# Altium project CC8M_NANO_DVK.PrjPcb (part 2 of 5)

## Sheet 06 - CCIMX8M Nano RF, PCIe.SchDoc: CCIMX8M Nano RF, PCIe
size A3; PageSetup: Record=PageOptions¦CenterHorizontal=True¦CenterVertical=True¦PrintScale=0.70¦XCorrection=1.00¦YCorrection=1.00¦PrintKind=0¦BorderSize=5000000¦LeftOffset=0¦BottomOffset=0¦Orientation=2¦PaperLength=4200¦PaperWidth=2970¦Scale=100¦PaperSource=7¦PrintQuality=600¦MediaType=1¦DitherType=10¦PaperKind=A4¦PrintScaleMode=1; Author: Juan Anzola; SheetNumber: 6; SheetTotal: 21

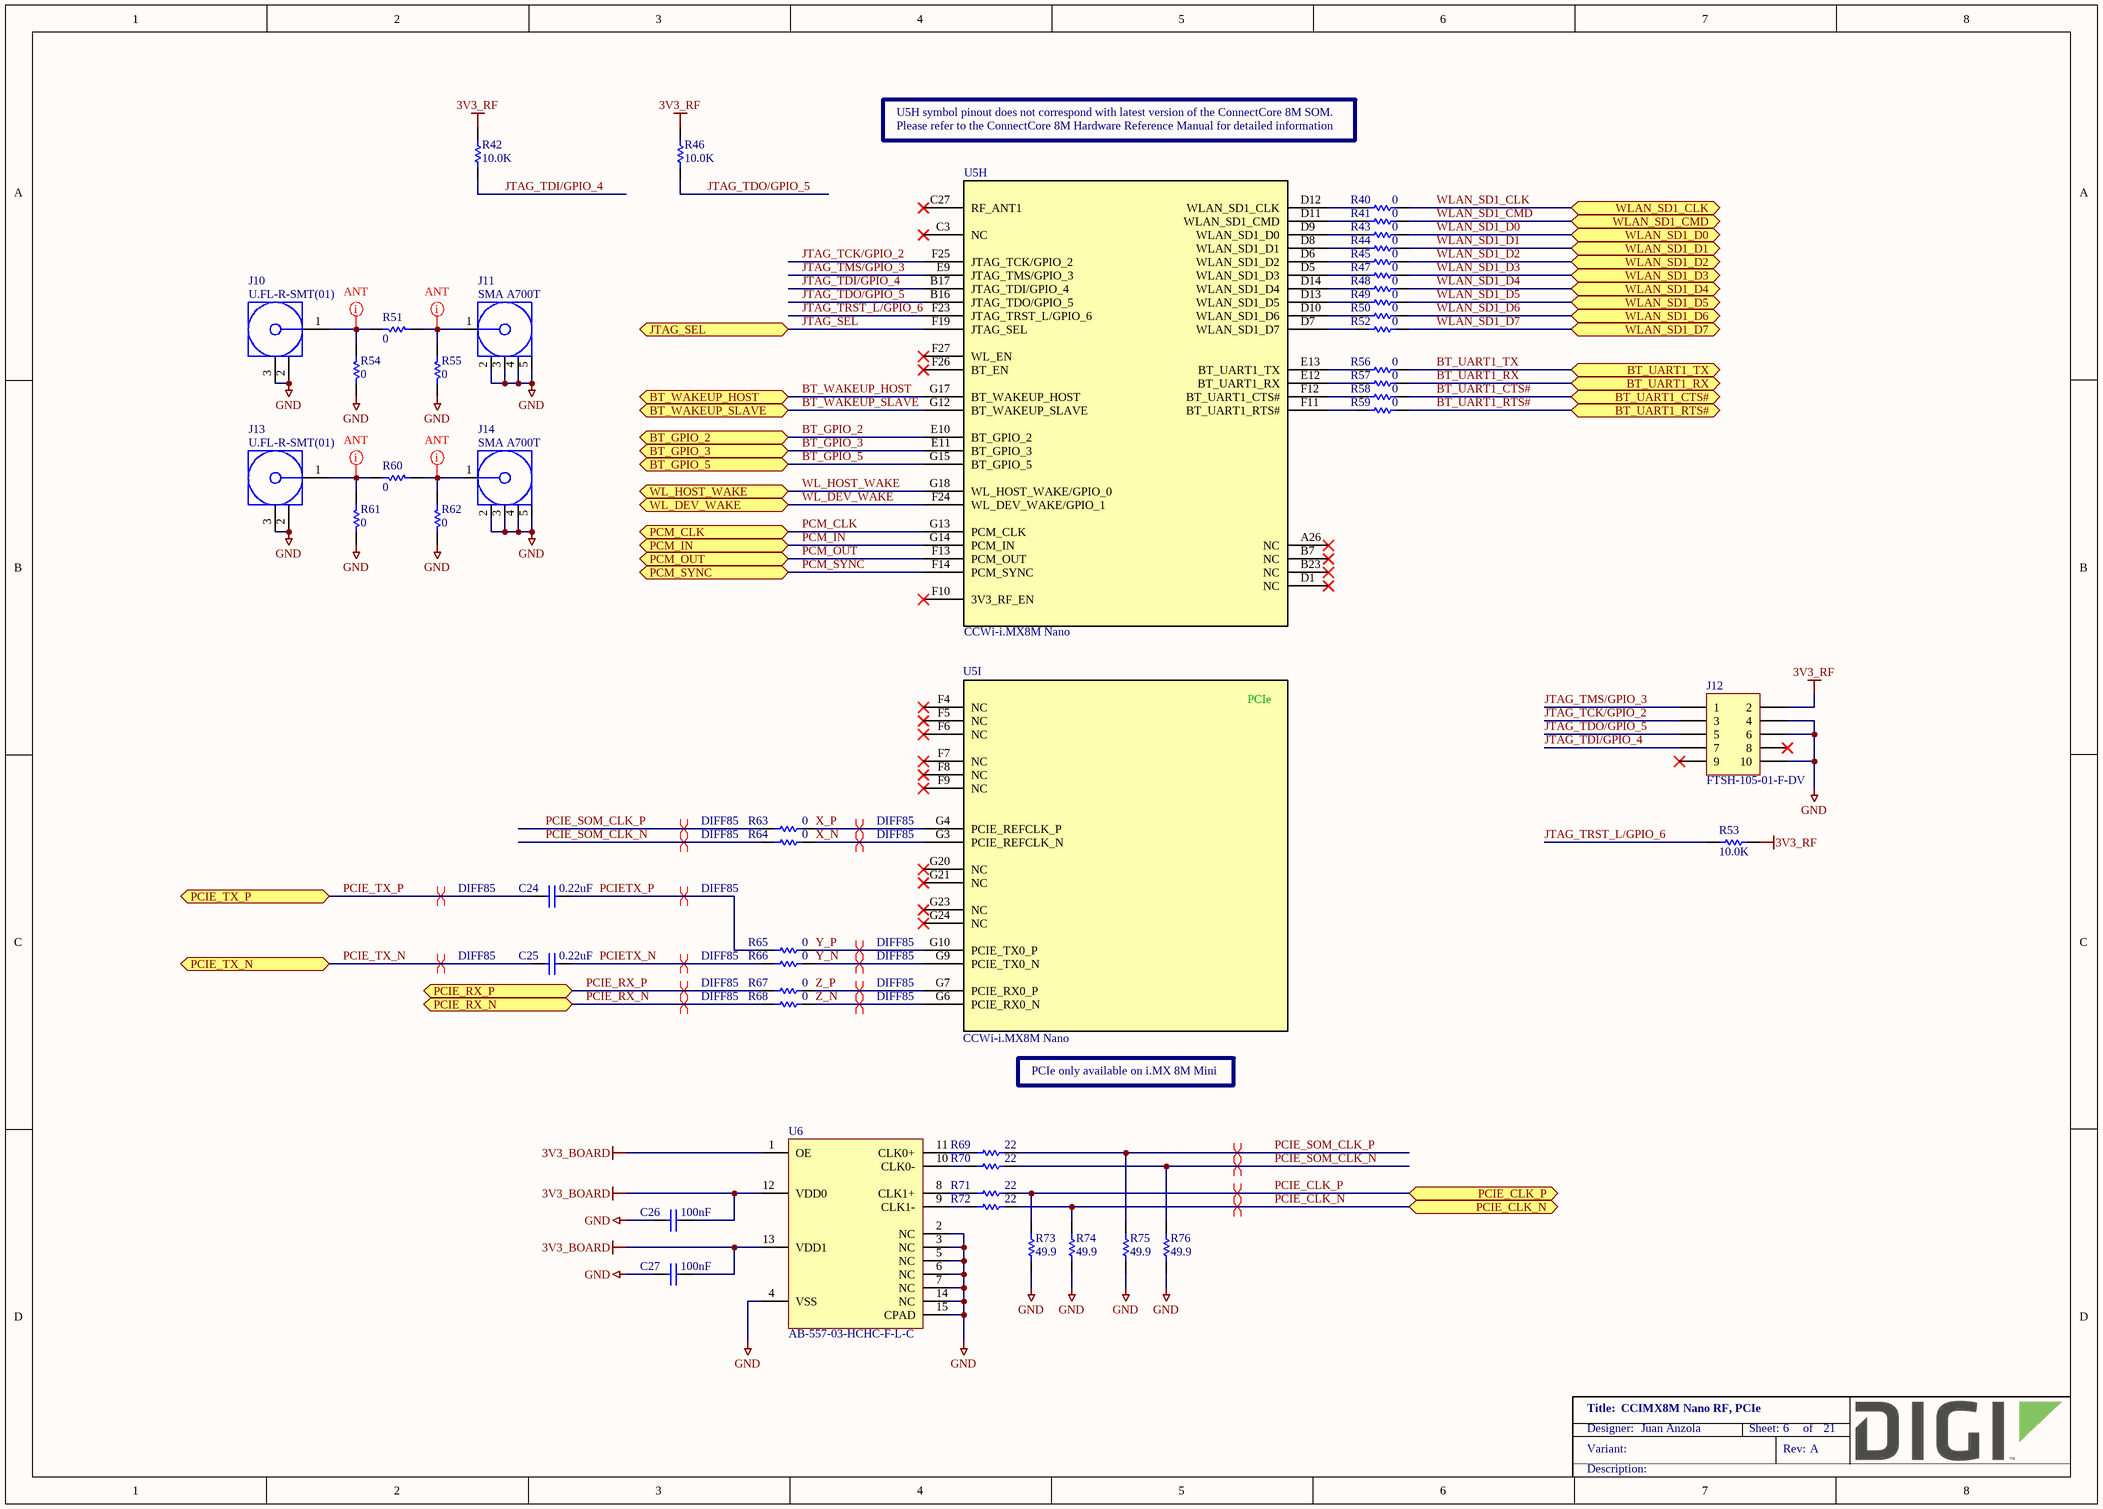
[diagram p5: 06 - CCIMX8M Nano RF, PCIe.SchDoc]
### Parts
C24  0.22uF  [CAPC1005X55N]
C25  0.22uF  [CAPC1005X55N]
C26  100nF  [CAPC1005X55N]
C27  100nF  [CAPC1005X55N]
J10  U.FL-R-SMT(01)  [HIROSE_U.FL-R-SMT(01)]
J11  SMA A700T  [BOBBINTRON_SMA A700T]
J12  FTSH-105-01-F-DV  [SAMTEC_FTSH-105-01-F-DV]
J13  U.FL-R-SMT(01)  [HIROSE_U.FL-R-SMT(01)]
J14  SMA A700T  [BOBBINTRON_SMA A700T]
R40  0  [RESC1005X40N]
R41  0  [RESC1005X40N]
R42  10.0K  [RESC1005X40N]
R43  0  [RESC1005X40N]
R44  0  [RESC1005X40N]
R45  0  [RESC1005X40N]
R46  10.0K  [RESC1005X40N]
R47  0  [RESC1005X40N]
R48  0  [RESC1005X40N]
R49  0  [RESC1005X40N]
R50  0  [RESC1005X40N]
R51  0  [RESC1005X40N]
R52  0  [RESC1005X40N]
R53  10.0K  [RESC1005X40N]
R54  0  [RESC1005X40N]
R55  0  [RESC1005X40N]
R56  0  [RESC1005X40N]
R57  0  [RESC1005X40N]
R58  0  [RESC1005X40N]
R59  0  [RESC1005X40N]
R60  0  [RESC1005X40N]
R61  0  [RESC1005X40N]
R62  0  [RESC1005X40N]
R63  0  [RESC1609X55N]
R64  0  [RESC1609X55N]
R65  0  [RESC1609X55N]
R66  0  [RESC1609X55N]
R67  0  [RESC1609X55N]
R68  0  [RESC1609X55N]
R69  22  [RESC1005X40N]
R70  22  [RESC1005X40N]
R71  22  [RESC1005X40N]
R72  22  [RESC1005X40N]
R73  49.9  [RESC1005X40N]
R74  49.9  [RESC1005X40N]
R75  49.9  [RESC1005X40N]
R76  49.9  [RESC1005X40N]
U5  CCWi-i.MX8M Nano  [E-TEC_LPJ474-129M-32ABEW55L]  (parts H,I of 10)
U6  AB-557-03-HCHC-F-L-C  [QFN50P320X250X90-15T140X210N]

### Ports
BT_GPIO_2 (bidir), BT_GPIO_3 (bidir), BT_GPIO_5 (bidir), BT_UART1_CTS# (bidir), BT_UART1_RTS# (bidir), BT_UART1_RX (bidir), BT_UART1_TX (bidir), BT_WAKEUP_HOST (bidir), BT_WAKEUP_SLAVE (bidir), JTAG_SEL (bidir), PCIE_CLK_N (bidir), PCIE_CLK_P (bidir), PCIE_RX_N (bidir), PCIE_RX_P (bidir), PCIE_TX_N (bidir), PCIE_TX_P (bidir), PCM_CLK (bidir), PCM_IN (bidir), PCM_OUT (bidir), PCM_SYNC (bidir), WL_DEV_WAKE (bidir), WL_HOST_WAKE (bidir), WLAN_SD1_CLK (bidir), WLAN_SD1_CMD (bidir), WLAN_SD1_D0 (bidir), WLAN_SD1_D1 (bidir), WLAN_SD1_D2 (bidir), WLAN_SD1_D3 (bidir), WLAN_SD1_D4 (bidir), WLAN_SD1_D5 (bidir), WLAN_SD1_D6 (bidir), WLAN_SD1_D7 (bidir)

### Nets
3V3_BOARD: C26.2 C27.2 U6.1(OE) U6.12(VDD0) U6.13(VDD1)
3V3_RF: J12.2 R42.2 R46.2 R53.2
GND: C26.1 C27.1 J10.2(GND) J10.3(GND) J11.2(GND) J11.3(GND) J11.4(GND) J11.5(GND) J12.4 J12.6 J12.10 J13.2(GND) J13.3(GND) J14.2(GND) J14.3(GND) J14.4(GND) J14.5(GND) R54.1 R55.1 R61.1 R62.1 R73.1 R74.1 R75.2 R76.2 U6.2(NC) U6.3(NC) U6.4(VSS) U6.5(NC) U6.6(NC) U6.7(NC) U6.14(NC) U6.15(CPAD)
BT_GPIO_2: U5.E10(BT_GPIO_2) ; port BT_GPIO_2
BT_GPIO_3: U5.E11(BT_GPIO_3) ; port BT_GPIO_3
BT_GPIO_5: U5.G15(BT_GPIO_5) ; port BT_GPIO_5
BT_UART1_CTS#: R58.2 ; port BT_UART1_CTS#
BT_UART1_RTS#: R59.2 ; port BT_UART1_RTS#
BT_UART1_RX: R57.2 ; port BT_UART1_RX
BT_UART1_TX: R56.2 ; port BT_UART1_TX
BT_WAKEUP_HOST: U5.G17(BT_WAKEUP_HOST) ; port BT_WAKEUP_HOST
BT_WAKEUP_SLAVE: U5.G12(BT_WAKEUP_SLAVE) ; port BT_WAKEUP_SLAVE
JTAG_SEL: U5.F19(JTAG_SEL) ; port JTAG_SEL
JTAG_TCK/GPIO_2: J12.3 U5.F25(JTAG_TCK/GPIO_2)
JTAG_TDI/GPIO_4: J12.7 R42.1 U5.B17(JTAG_TDI/GPIO_4)
JTAG_TDO/GPIO_5: J12.5 R46.1 U5.B16(JTAG_TDO/GPIO_5)
JTAG_TMS/GPIO_3: J12.1 U5.E9(JTAG_TMS/GPIO_3)
JTAG_TRST_L/GPIO_6: R53.1 U5.F23(JTAG_TRST_L/GPIO_6)
PCIE_CLK_N: R72.2 R74.2 ; port PCIE_CLK_N
PCIE_CLK_P: R71.2 R73.2 ; port PCIE_CLK_P
PCIE_RX_N: R68.1 ; port PCIE_RX_N
PCIE_RX_P: R67.1 ; port PCIE_RX_P
PCIE_SOM_CLK_N: R64.1 R70.2 R76.1
PCIE_SOM_CLK_P: R63.1 R69.2 R75.1
PCIE_TX_N: C25.2 ; port PCIE_TX_N
PCIE_TX_P: C24.2 ; port PCIE_TX_P
PCIETX_N: C25.1 R66.1
PCIETX_P: C24.1 R65.1
PCM_CLK: U5.G13(PCM_CLK) ; port PCM_CLK
PCM_IN: U5.G14(PCM_IN) ; port PCM_IN
PCM_OUT: U5.F13(PCM_OUT) ; port PCM_OUT
PCM_SYNC: U5.F14(PCM_SYNC) ; port PCM_SYNC
WL_DEV_WAKE: U5.F24(WL_DEV_WAKE/GPIO_1) ; port WL_DEV_WAKE
WL_HOST_WAKE: U5.G18(WL_HOST_WAKE/GPIO_0) ; port WL_HOST_WAKE
WLAN_SD1_CLK: R40.2 ; port WLAN_SD1_CLK
WLAN_SD1_CMD: R41.2 ; port WLAN_SD1_CMD
WLAN_SD1_D0: R43.2 ; port WLAN_SD1_D0
WLAN_SD1_D1: R44.2 ; port WLAN_SD1_D1
WLAN_SD1_D2: R45.2 ; port WLAN_SD1_D2
WLAN_SD1_D3: R47.2 ; port WLAN_SD1_D3
WLAN_SD1_D4: R48.2 ; port WLAN_SD1_D4
WLAN_SD1_D5: R49.2 ; port WLAN_SD1_D5
WLAN_SD1_D6: R50.2 ; port WLAN_SD1_D6
WLAN_SD1_D7: R52.2 ; port WLAN_SD1_D7
X_N: R64.2 U5.G3(PCIE_REFCLK_N)
X_P: R63.2 U5.G4(PCIE_REFCLK_P)
Y_N: R66.2 U5.G9(PCIE_TX0_N)
Y_P: R65.2 U5.G10(PCIE_TX0_P)
Z_N: R68.2 U5.G6(PCIE_RX0_N)
Z_P: R67.2 U5.G7(PCIE_RX0_P)
NetJ10_1: J10.1(Signal) R51.2 R54.2
NetJ11_1: J11.1(Signal) R51.1 R55.2
NetJ13_1: J13.1(Signal) R60.2 R61.2
NetJ14_1: J14.1(Signal) R60.1 R62.2
NetR40_1: R40.1 U5.D12(WLAN_SD1_CLK)
NetR41_1: R41.1 U5.D11(WLAN_SD1_CMD)
NetR43_1: R43.1 U5.D9(WLAN_SD1_D0)
NetR44_1: R44.1 U5.D8(WLAN_SD1_D1)
NetR45_1: R45.1 U5.D6(WLAN_SD1_D2)
NetR47_1: R47.1 U5.D5(WLAN_SD1_D3)
NetR48_1: R48.1 U5.D14(WLAN_SD1_D4)
NetR49_1: R49.1 U5.D13(WLAN_SD1_D5)
NetR50_1: R50.1 U5.D10(WLAN_SD1_D6)
NetR52_1: R52.1 U5.D7(WLAN_SD1_D7)
NetR56_1: R56.1 U5.E13(BT_UART1_TX)
NetR57_1: R57.1 U5.E12(BT_UART1_RX)
NetR58_1: R58.1 U5.F12(BT_UART1_CTS#)
NetR59_1: R59.1 U5.F11(BT_UART1_RTS#)
NetR69_1: R69.1 U6.11(CLK0+)
NetR70_1: R70.1 U6.10(CLK0-)
NetR71_1: R71.1 U6.8(CLK1+)
NetR72_1: R72.1 U6.9(CLK1-)

Not connected (* = marked no-connect by the designer): J12 8* 9*; U5 A26(NC)* B7(NC)* B23(NC)* C3(NC)* C27(RF_ANT1)* D1(NC)* F4(NC)* F5(NC)* F6(NC)* F7(NC)* F8(NC)* F9(NC)* F10(3V3_RF_EN)* F26(BT_EN)* F27(WL_EN)* G20(NC)* G21(NC)* G23(NC)* G24(NC)*

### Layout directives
differential pair; net class DIFF85: PCIE_RX_N, PCIE_RX_P, PCIE_SOM_CLK_N, PCIE_SOM_CLK_P, PCIE_TX_N, PCIE_TX_P, PCIETX_N, PCIETX_P, X_N, X_P, Y_N, Y_P, Z_N, Z_P
differential pair: PCIE_CLK_N, PCIE_CLK_P, PCIE_SOM_CLK_N, PCIE_SOM_CLK_P
net class ANT: NetJ10_1, NetJ11_1, NetJ13_1, NetJ14_1

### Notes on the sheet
- U5H symbol pinout does not correspond with latest version of the ConnectCore 8M SOM.
- Please refer to the ConnectCore 8M Hardware Reference Manual for detailed information
- PCIe only available on i.MX 8M Mini

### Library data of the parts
C24 C25 = 1001883: CAP CER 0.22UF 6.3V X7R 0402; Part_Type: Capacitor; Manufacturer: Taiyo Yuden; Manufacturer_Part_Number: JMK105B7224KV-F; Digi_PN: 14000067; Component_Life_Cycle_State: Reviewed; Area: 2.2; Project: Powerley Energy Bridge; Tolerance: 10%
C26 C27 = 1000006: CAP 100nF 16V 10% X7R 0402; Part_Type: Capacitor; Manufacturer: Murata; Manufacturer_Part_Number: GRM155R71C104KA88D; Digi_PN: 14050552; Component_Life_Cycle_State: CAD Reviewed; Area: 0.95; Project: KITT; Tolerance: 10
J10 J13 = 1000027: RF Connectors U.FL RECEPTACLE SMT GLD M CONTACT; Manufacturer: Hirose; Digi_PN: 18000684; Component_Life_Cycle_State: Proven; Area: 14,4
J11 J14 = 1002720: CONN SMA JACK R/A 50 OHM L15.1MM PCB TH; Part_Type: Connector; Manufacturer: Bobbintron Electrical Corp; Digi_PN: MA02979; Component_Life_Cycle_State: Reviewed; Area: 121,68
J12 = 1000034: CONN HEADER 10POS DUAL .05" SMD; Part_Type: Connector; Manufacturer: Samtec; Note: 18000715 = Digi No. for GE WDNU; Digi_PN: 18000539; Component_Life_Cycle_State: Proven; Area: 43,55
R40 R41 R43-R45 R47-R50 R52 R56-R59 = 1000076: RES 0.0 OHM 1/10W 0402 SMD; Part_Type: Resistor; Manufacturer: Panasonic - ECG; Manufacturer_Part_Number: ERJ-2GE0R00X; Component_Life_Cycle_State: Proven; Area: 0.95; Project: Adjustable Foundation; Power_WV_SRF: 10; Digi_PN: 13050387
R42 R46 R53 = 1000537: RES 10.0K OHM 1/10W 1% 0402 SMD; Part_Type: Resistor; Manufacturer: Panasonic - ECG; Manufacturer_Part_Number: ERJ-2RKF1002X; Digi_PN: 13051084; Component_Life_Cycle_State: CAD Reviewed; Area: 0,95; Power_WV_SRF: 100
R51 R54 R55 R60-R62 = 1000076: RES 0.0 OHM 1/10W 0402 SMD; Part_Type: Resistor; Manufacturer: Panasonic - ECG; Manufacturer_Part_Number: ERJ-2GE0R00X; Digi_PN: 13050387; Component_Life_Cycle_State: Proven; Area: 0,95; Project: Adjustable Foundation; Power_WV_SRF: 10
R63-R68 = 1000208: RES 0.0 OHM 1/10W 0603; Part_Type: Resistor; Manufacturer: Panasonic - ECG; Manufacturer_Part_Number: ERJ-3GEY0R00V; Note: 13051103 = Digi No. for GE WDNU; Digi_PN: 13050568; Component_Life_Cycle_State: Reviewed; Area: 2,5; Voltage: 75V
R69-R72 = 1000601: RES 22.0 OHM 1/10W 1% 0402 SMD; Part_Type: Resistor; Manufacturer: Panasonic - ECG; Manufacturer_Part_Number: ERJ-2RKF22R0X; Digi_PN: 13051089; Component_Life_Cycle_State: CAD Reviewed; Area: 0.95; Project: KITT; Power_WV_SRF: 100
R73-R76 = 1000466: RES 49.9 OHM 1/10W 1% 0402 SMD; Part_Type: Resistor; Manufacturer: Panasonic - ECG; Manufacturer_Part_Number: ERJ-2RKF49R9X; Digi_PN: 13051083; Component_Life_Cycle_State: CAD Reviewed; Area: 0.95; Project: KITT; Power_WV_SRF: 100
U5 = 1002739: ConnectCore for i.MX8M Nano module - LGA; Manufacturer: DIGI; Digi_PN: 50002014-01; Component_Life_Cycle_State: Pending
U6 = 1002449: SMIC PCIE CLOCK GEN 100MHZ 14QFN; Part_Type: IC; Manufacturer: Abracon Corporation; Digi_PN: 16000101; Component_Life_Cycle_State: Created; Area: 16; Project: DIGI CC8X SOM

## Sheet 07 - Bootstrap.SchDoc: Bootstrap
size A3; PageSetup: Record=PageOptions¦CenterHorizontal=True¦CenterVertical=True¦PrintScale=0.70¦XCorrection=1.00¦YCorrection=1.00¦PrintKind=0¦BorderSize=5000000¦LeftOffset=0¦BottomOffset=0¦Orientation=2¦PaperLength=4200¦PaperWidth=2970¦Scale=100¦PaperSource=7¦PrintQuality=600¦MediaType=1¦DitherType=10¦PaperKind=A4¦PrintScaleMode=1; Author: Juan Anzola; SheetNumber: 7; SheetTotal: 21

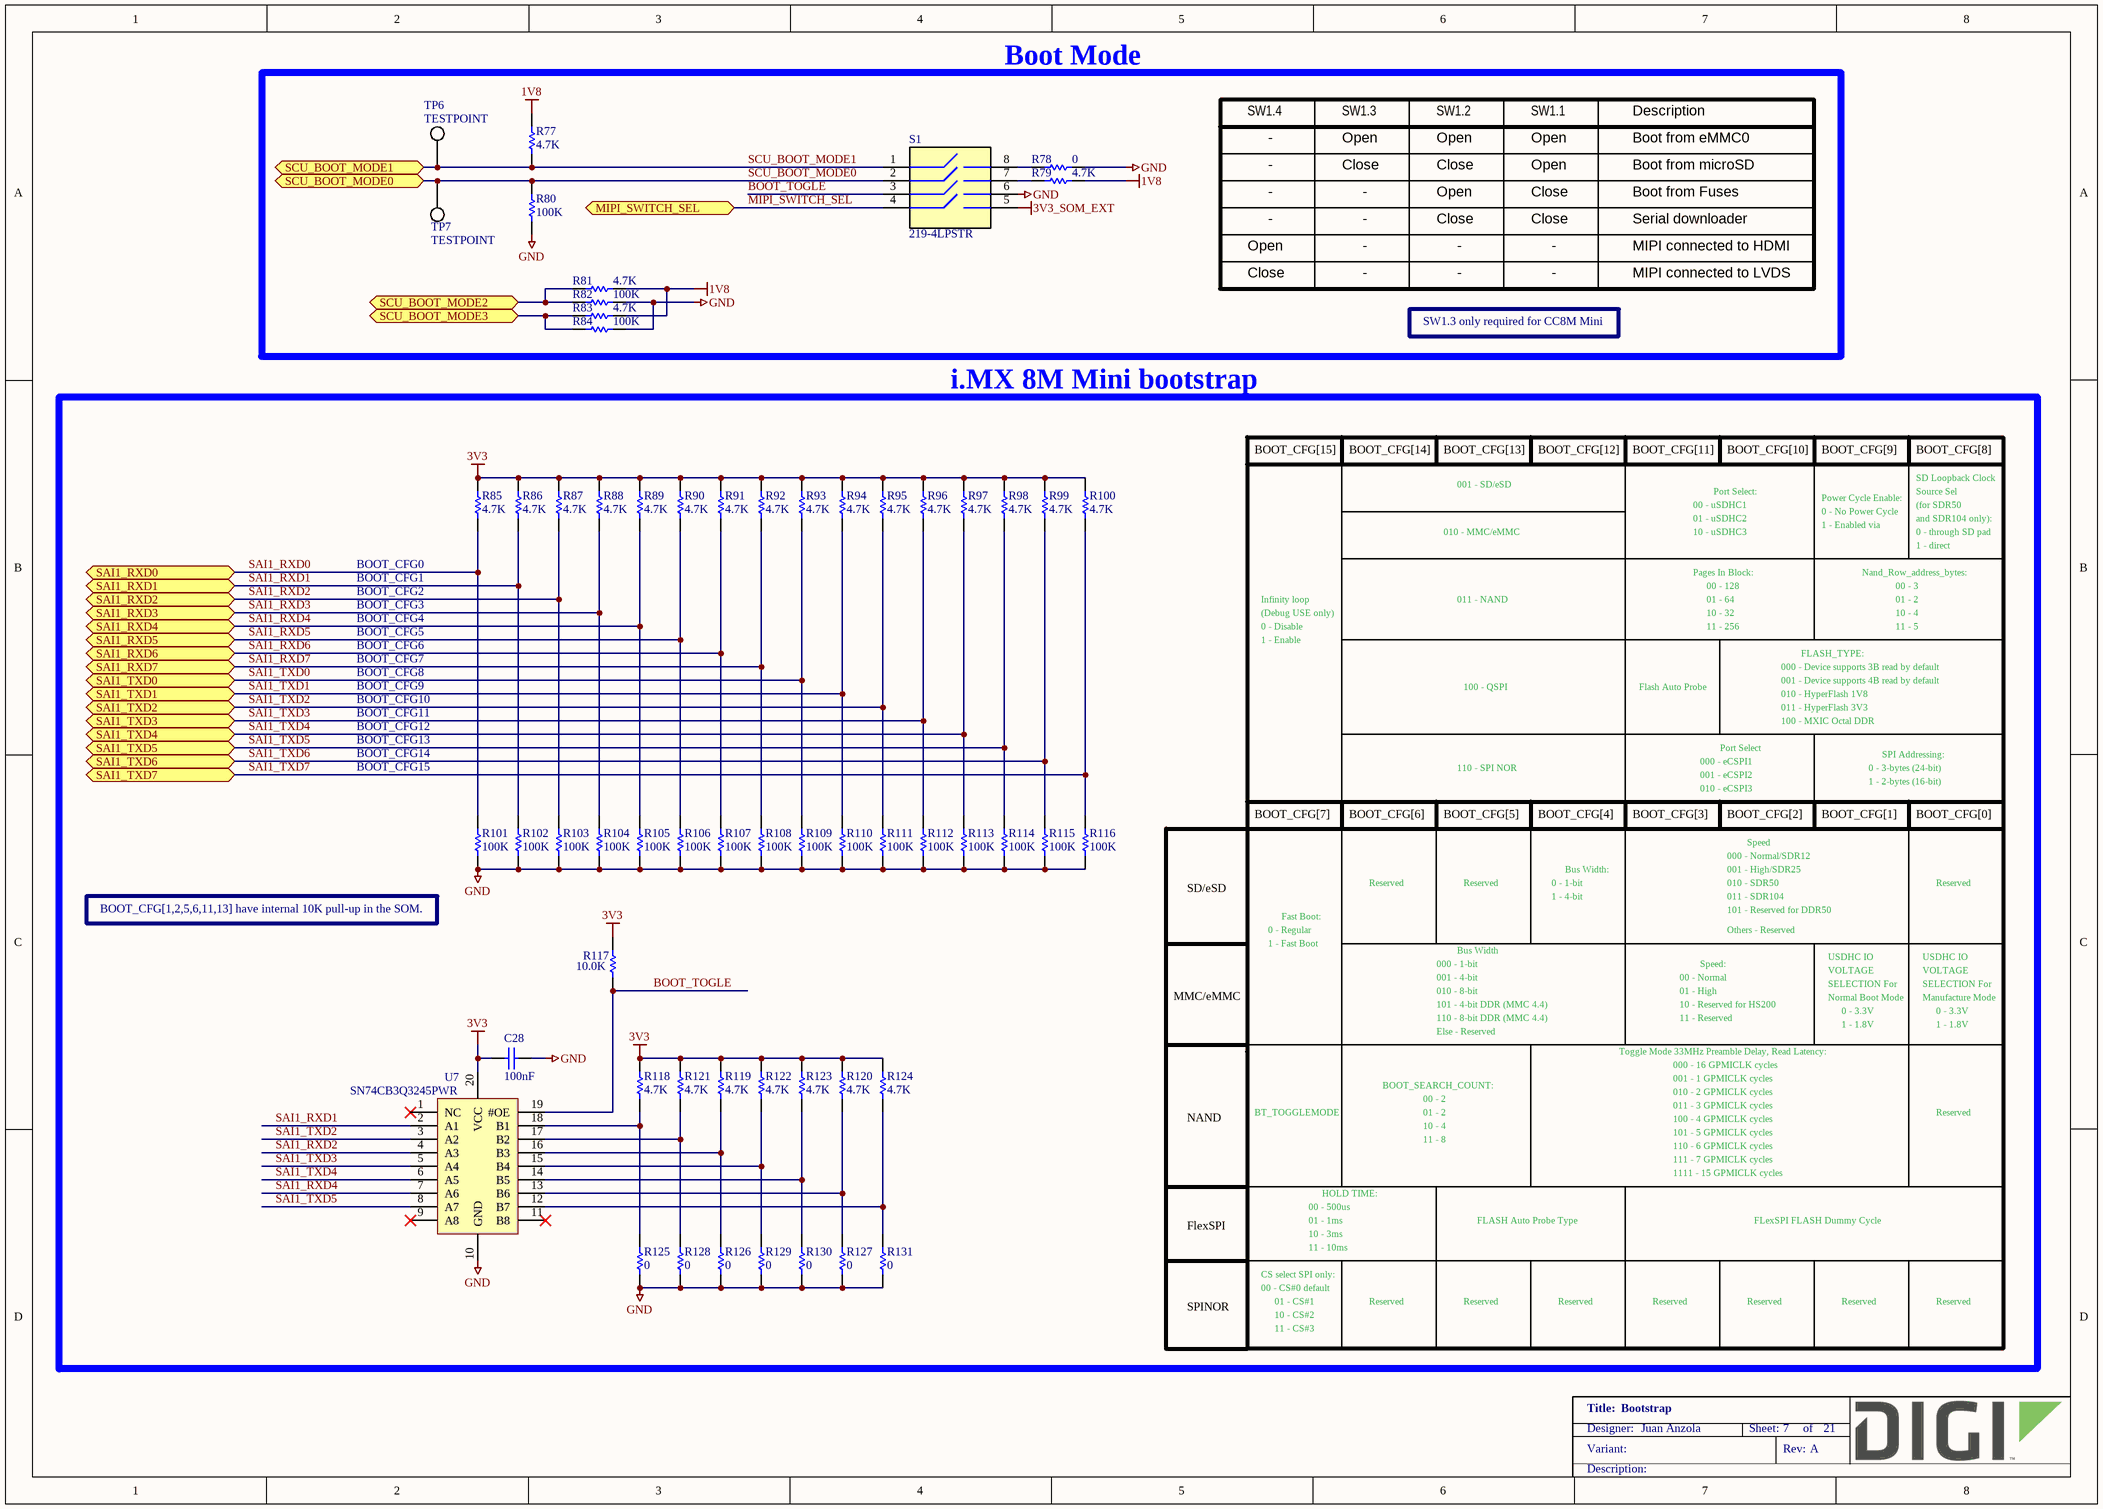
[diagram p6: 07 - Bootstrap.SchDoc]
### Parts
C28  100nF  [CAPC1005X55N]
R77  4.7K  [RESC1005X40N]
R78  0  [RESC1005X40N]
R79  4.7K  [RESC1005X40N]
R80  100K  [RESC1005X40N]
R81  4.7K  [RESC1005X40N]
R82  100K  [RESC1005X40N]
R83  4.7K  [RESC1005X40N]
R84  100K  [RESC1005X40N]
R85  4.7K  [RESC1005X40N]
R86  4.7K  [RESC1005X40N]
R87  4.7K  [RESC1005X40N]
R88  4.7K  [RESC1005X40N]
R89  4.7K  [RESC1005X40N]
R90  4.7K  [RESC1005X40N]
R91  4.7K  [RESC1005X40N]
R92  4.7K  [RESC1005X40N]
R93  4.7K  [RESC1005X40N]
R94  4.7K  [RESC1005X40N]
R95  4.7K  [RESC1005X40N]
R96  4.7K  [RESC1005X40N]
R97  4.7K  [RESC1005X40N]
R98  4.7K  [RESC1005X40N]
R99  4.7K  [RESC1005X40N]
R100  4.7K  [RESC1005X40N]
R101  100K  [RESC1005X40N]
R102  100K  [RESC1005X40N]
R103  100K  [RESC1005X40N]
R104  100K  [RESC1005X40N]
R105  100K  [RESC1005X40N]
R106  100K  [RESC1005X40N]
R107  100K  [RESC1005X40N]
R108  100K  [RESC1005X40N]
R109  100K  [RESC1005X40N]
R110  100K  [RESC1005X40N]
R111  100K  [RESC1005X40N]
R112  100K  [RESC1005X40N]
R113  100K  [RESC1005X40N]
R114  100K  [RESC1005X40N]
R115  100K  [RESC1005X40N]
R116  100K  [RESC1005X40N]
R117  10.0K  [RESC1005X40N]
R118  4.7K  [RESC1005X40N]
R119  4.7K  [RESC1005X40N]
R120  4.7K  [RESC1005X40N]
R121  4.7K  [RESC1005X40N]
R122  4.7K  [RESC1005X40N]
R123  4.7K  [RESC1005X40N]
R124  4.7K  [RESC1005X40N]
R125  0  [RESC1005X40N]
R126  0  [RESC1005X40N]
R127  0  [RESC1005X40N]
R128  0  [RESC1005X40N]
R129  0  [RESC1005X40N]
R130  0  [RESC1005X40N]
R131  0  [RESC1005X40N]
S1  219-4LPSTR  [SOIC254P991X420-8N]
TP6  TESTPOINT  [TP0762]  (no BOM)
TP7  TESTPOINT  [TP0762]  (no BOM)
U7  SN74CB3Q3245PWR  [SOP65P640X120-20N]

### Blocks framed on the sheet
Boot Mode: R77-R84 S1 TP6 TP7
i.MX 8M Mini bootstrap: C28 R85-R131 U7

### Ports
MIPI_SWITCH_SEL (bidir), SAI1_RXD0 (bidir), SAI1_RXD1 (bidir), SAI1_RXD2 (bidir), SAI1_RXD3 (bidir), SAI1_RXD4 (bidir), SAI1_RXD5 (bidir), SAI1_RXD6 (bidir), SAI1_RXD7 (bidir), SAI1_TXD0 (bidir), SAI1_TXD1 (bidir), SAI1_TXD2 (bidir), SAI1_TXD3 (bidir), SAI1_TXD4 (bidir), SAI1_TXD5 (bidir), SAI1_TXD6 (bidir), SAI1_TXD7 (bidir), SCU_BOOT_MODE0 (bidir), SCU_BOOT_MODE1 (bidir), SCU_BOOT_MODE2 (bidir), SCU_BOOT_MODE3 (bidir)

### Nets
1V8: R77.2 R79.2 R81.1 R83.1
3V3: C28.2 R85.1 R86.1 R87.1 R88.1 R89.1 R90.1 R91.1 R92.1 R93.1 R94.1 R95.1 R96.1 R97.1 R98.1 R99.1 R100.1 R117.1 R118.1 R119.1 R120.1 R121.1 R122.1 R123.1 R124.1 U7.20(VCC)
3V3_SOM_EXT: S1.5
GND: C28.1 R78.2 R80.1 R82.1 R84.1 R101.2 R102.2 R103.2 R104.2 R105.2 R106.2 R107.2 R108.2 R109.2 R110.2 R111.2 R112.2 R113.2 R114.2 R115.2 R116.2 R125.1 R126.1 R127.1 R128.1 R129.1 R130.1 R131.1 S1.6 U7.10(GND)
BOOT_TOGLE: R117.2 S1.3 U7.19(#OE)
MIPI_SWITCH_SEL: S1.4 ; port MIPI_SWITCH_SEL
SAI1_RXD0: R85.2 R101.1 ; port SAI1_RXD0
SAI1_RXD1: R86.2 R102.1 U7.2(A1) ; port SAI1_RXD1
SAI1_RXD2: R87.2 R103.1 U7.4(A3) ; port SAI1_RXD2
SAI1_RXD3: R88.2 R104.1 ; port SAI1_RXD3
SAI1_RXD4: R89.2 R105.1 U7.7(A6) ; port SAI1_RXD4
SAI1_RXD5: R90.2 R106.1 ; port SAI1_RXD5
SAI1_RXD6: R91.2 R107.1 ; port SAI1_RXD6
SAI1_RXD7: R92.2 R108.1 ; port SAI1_RXD7
SAI1_TXD0: R93.2 R109.1 ; port SAI1_TXD0
SAI1_TXD1: R94.2 R110.1 ; port SAI1_TXD1
SAI1_TXD2: R95.2 R111.1 U7.3(A2) ; port SAI1_TXD2
SAI1_TXD3: R96.2 R112.1 U7.5(A4) ; port SAI1_TXD3
SAI1_TXD4: R97.2 R113.1 U7.6(A5) ; port SAI1_TXD4
SAI1_TXD5: R98.2 R114.1 U7.8(A7) ; port SAI1_TXD5
SAI1_TXD6: R99.2 R115.1 ; port SAI1_TXD6
SAI1_TXD7: R100.2 R116.1 ; port SAI1_TXD7
SCU_BOOT_MODE0: R80.2 S1.2 TP7.1 ; port SCU_BOOT_MODE0
SCU_BOOT_MODE1: R77.1 S1.1 TP6.1 ; port SCU_BOOT_MODE1
SCU_BOOT_MODE2: R81.2 R82.2 ; port SCU_BOOT_MODE2
SCU_BOOT_MODE3: R83.2 R84.2 ; port SCU_BOOT_MODE3
NetR78_1: R78.1 S1.8
NetR79_1: R79.1 S1.7
NetR118_2: R118.2 R125.2 U7.18(B1)
NetR119_2: R119.2 R126.2 U7.16(B3)
NetR120_2: R120.2 R127.2 U7.13(B6)
NetR121_2: R121.2 R128.2 U7.17(B2)
NetR122_2: R122.2 R129.2 U7.15(B4)
NetR123_2: R123.2 R130.2 U7.14(B5)
NetR124_2: R124.2 R131.2 U7.12(B7)

Not connected (* = marked no-connect by the designer): U7 1(NC)* 9(A8)* 11(B8)*

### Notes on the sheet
- SW1.4
- -
- SW1.3
- Open
- Close
- SW1.2
- SW1.1
- Description
- Boot from eMMC0
- Boot from microSD
- Boot from Fuses
- Serial downloader
- MIPI connected to HDMI
- MIPI connected to LVDS
- SW1.3 only required for CC8M Mini
- BOOT_CFG[15]
- BOOT_CFG[14]
- BOOT_CFG[13]
- BOOT_CFG[12]
- BOOT_CFG[11]
- BOOT_CFG[10]
- BOOT_CFG[9]
- BOOT_CFG[8]
- 001 - SD/eSD
- 00 - uSDHC1
- Port Select:
- Power Cycle Enable:
- 0 - No Power Cycle
- SD Loopback Clock
- Source Sel
- (for SDR50
- BOOT_CFG0
- BOOT_CFG1
- 010 - MMC/eMMC
- 01 - uSDHC2
- 10 - uSDHC3
- Pages In Block:
- 00 - 128
- 1 - Enabled via
- Nand_Row_address_bytes:
- 00 - 3
- and SDR104 only):
- 0 - through SD pad
- 1 - direct
- BOOT_CFG2
- BOOT_CFG3
- BOOT_CFG4
- BOOT_CFG5
- BOOT_CFG6
- Infinity loop
- (Debug USE only)
- 0 - Disable
- 1 - Enable
- 011 - NAND
- 01 - 64
- 10 - 32
- 11 - 256
- 01 - 2
- 11 - 5
- 10 - 4
- BOOT_CFG7
- BOOT_CFG8
- BOOT_CFG9
- BOOT_CFG11
- BOOT_CFG10
- 100 - QSPI
- Flash Auto Probe
- 000 - Device supports 3B read by default
- 001 - Device supports 4B read by default
- 010 - HyperFlash 1V8
- 100 - MXIC Octal DDR
- 011 - HyperFlash 3V3
- FLASH_TYPE:
- BOOT_CFG12
- BOOT_CFG13
- BOOT_CFG14
- BOOT_CFG15
- 110 - SPI NOR
- 000 - eCSPI1
- 001 - eCSPI2
- Port Select
- 0 - 3-bytes (24-bit)
- 1 - 2-bytes (16-bit)
- SPI Addressing:
- BOOT_CFG[7]
- BOOT_CFG[6]
- BOOT_CFG[5]
- BOOT_CFG[4]
- BOOT_CFG[3]
- 010 - eCSPI3
- BOOT_CFG[2]
- 000 - Normal/SDR12
- Speed
- BOOT_CFG[1]
- BOOT_CFG[0]
- BOOT_CFG[1,2,5,6,11,13] have internal 10K pull-up in the SOM.
- SD/eSD
- Fast Boot:
- Reserved
- 0 - 1-bit
- 1 - 4-bit
- Bus Width:
- 001 - High/SDR25
- 010 - SDR50
- 011 - SDR104
- 101 - Reserved for DDR50
- 0 - Regular
- 1 - Fast Boot
- 000 - 1-bit
- 001 - 4-bit
- 010 - 8-bit
- Bus Width
- 00 - Normal
- 01 - High
- Speed:
- Others - Reserved
- USDHC IO
- SELECTION For
- VOLTAGE
- MMC/eMMC
- 101 - 4-bit DDR (MMC 4.4)
- 110 - 8-bit DDR (MMC 4.4)
- Else - Reserved
- Toggle Mode 33MHz Preamble Delay, Read Latency:
- 10 - Reserved for HS200
- 11 - Reserved
- Normal Boot Mode
- 0 - 3.3V
- 1 - 1.8V
- Manufacture Mode
- NAND
- BT_TOGGLEMODE
- BOOT_SEARCH_COUNT:
- 00 - 2
- 000 - 16 GPMICLK cycles
- 001 - 1 GPMICLK cycles
- 010 - 2 GPMICLK cycles
- 011 - 3 GPMICLK cycles
- 100 - 4 GPMICLK cycles
- 11 - 8
- 101 - 5 GPMICLK cycles
- 110 - 6 GPMICLK cycles
- 111 - 7 GPMICLK cycles
- 1111 - 15 GPMICLK cycles
- FlexSPI
- 00 - 500us
- 01 - 1ms
- 10 - 3ms
- 11 - 10ms
- HOLD TIME:
- FLASH Auto Probe Type
- FLexSPI FLASH Dummy Cycle
- SPINOR
- CS select SPI only:
- 00 - CS#0 default
- 01 - CS#1
- 10 - CS#2
- 11 - CS#3

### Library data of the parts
C28 = 1000006: CAP 100nF 16V 10% X7R 0402; Part_Type: Capacitor; Manufacturer: Murata; Manufacturer_Part_Number: GRM155R71C104KA88D; Component_Life_Cycle_State: CAD Reviewed; Area: 0.95; Project: KITT; Tolerance: 10; Digi_PN: 14050552
R77 R79 R81 R83 R85-R100 R118-R124 = 1000038: RES 4.7K OHM 1/10W 5% 0402 SMD; Part_Type: Resistor; Manufacturer: Panasonic - ECG; Manufacturer_Part_Number: ERJ-2GEJ472X; Digi_PN: 13050549; Component_Life_Cycle_State: Proven; Area: 0,95; Project: Adjustable Foundation; Power_WV_SRF: 100; Tolerance: 5
R78 R125-R131 = 1000076: as R40 on sheet 06 - CCIMX8M Nano RF, PCIe
R80 R82 R84 R101-R116 = 1000480: RES 100K OHM 1/10W 1% 0402 SMD; Part_Type: Resistor; Manufacturer: Panasonic - ECG; Manufacturer_Part_Number: ERJ-2RKF1003X; Digi_PN: 13051063; Component_Life_Cycle_State: CAD Reviewed; Area: 0,95; Project: KITT; Power_WV_SRF: 100
R117 = 1000537: RES 10.0K OHM 1/10W 1% 0402 SMD; Part_Type: Resistor; Manufacturer: Panasonic - ECG; Manufacturer_Part_Number: ERJ-2RKF1002X; Component_Life_Cycle_State: CAD Reviewed; Area: 0.95; Project: KITT; Power_WV_SRF: 100; Digi_PN: 13051084
S1 = 1002122: SWITCH SLIDE DIP SPST 100MA 20V; Manufacturer: CTS; Digi_PN: 22000318; Component_Life_Cycle_State: Created; Area: 155
TP6 TP7 = CAD0011: TEST POINT 30MIL PAD SMT; Component_Life_Cycle_State: Reviewed; Area: 0,58; Project: CLC
U7 = 1001368: IC SWITCH BUS 8BIT FET 20-TSSOP; Manufacturer: Texas Instruments; Digi_PN: 16052042; Component_Life_Cycle_State: Reviewed; Area: 48,18; Project: ConnectCore i.MX6x SOM

## Sheet 08 - Consoles.SchDoc: Consoles
size A3; PageSetup: Record=PageOptions¦CenterHorizontal=True¦CenterVertical=True¦PrintScale=0.70¦XCorrection=1.00¦YCorrection=1.00¦PrintKind=0¦BorderSize=5000000¦LeftOffset=0¦BottomOffset=0¦Orientation=2¦PaperLength=4200¦PaperWidth=2970¦Scale=100¦PaperSource=7¦PrintQuality=600¦MediaType=1¦DitherType=10¦PaperKind=A4¦PrintScaleMode=1; Author: Juan Anzola; SheetNumber: 8; SheetTotal: 21

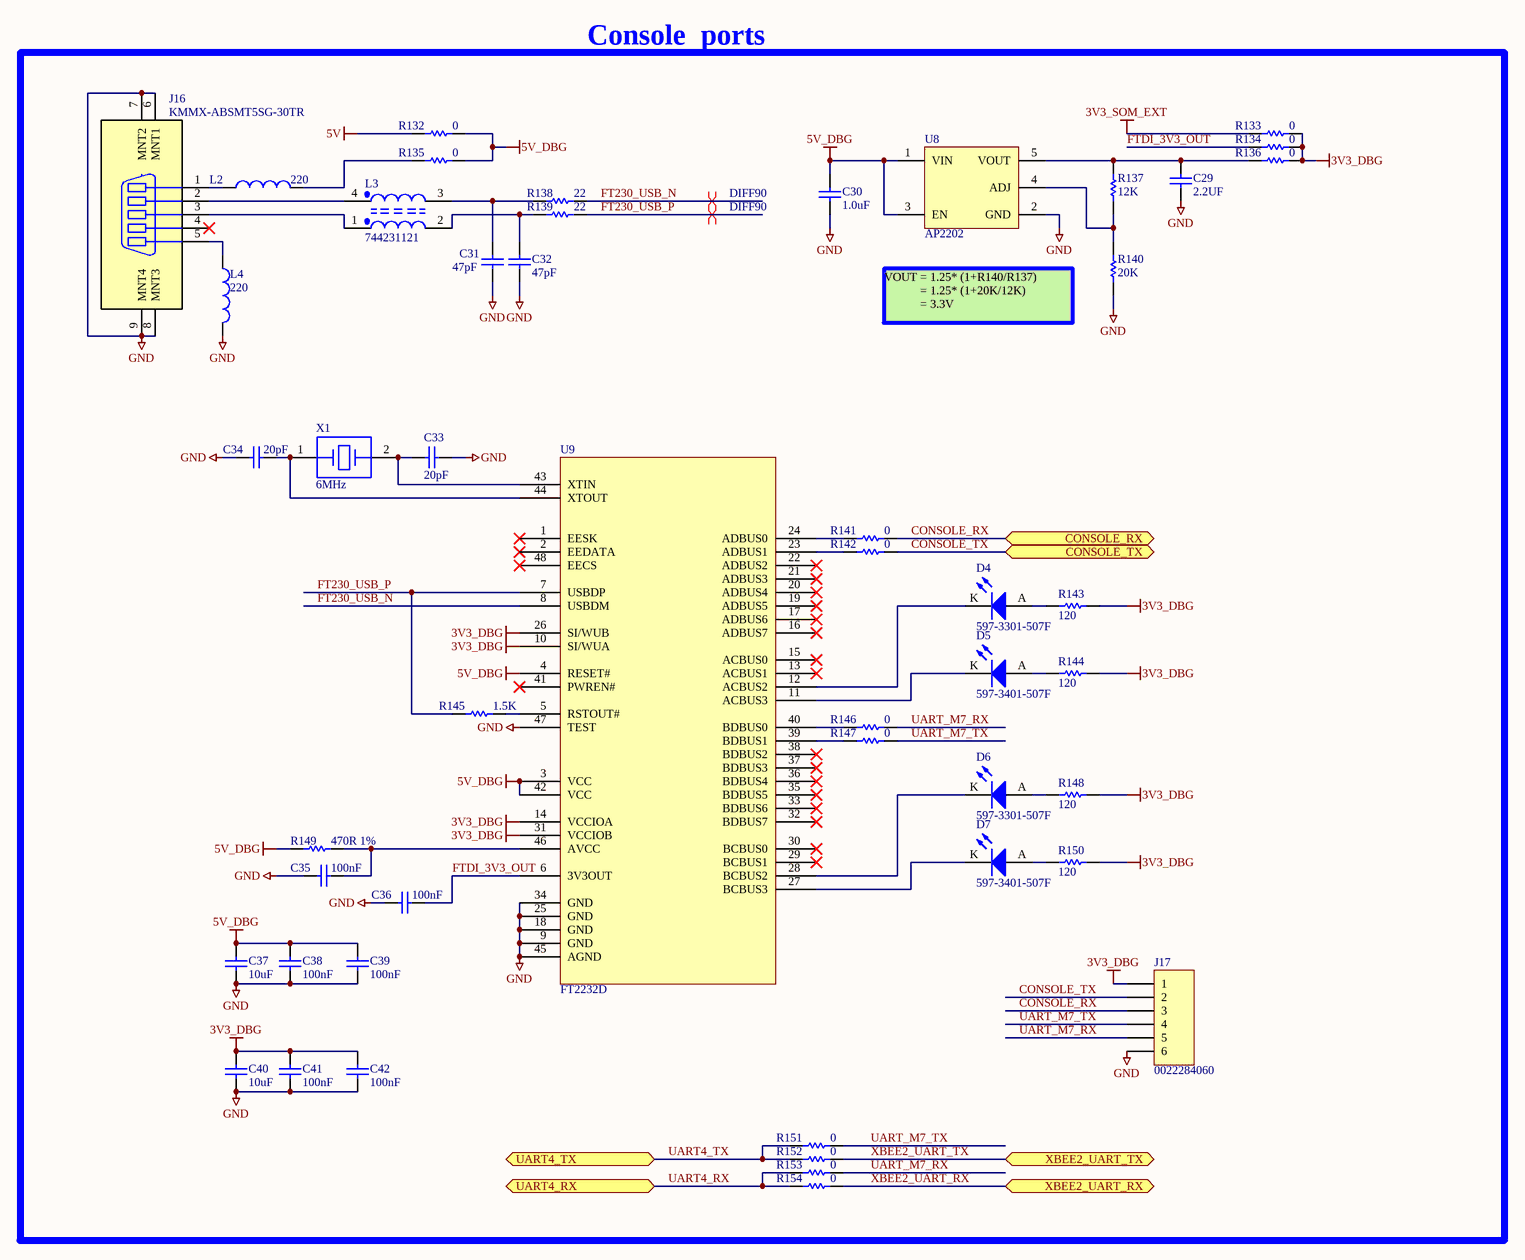
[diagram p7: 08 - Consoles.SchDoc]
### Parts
C29  2.2UF  [CAPC1608X90N]
C30  1.0uF  [CAPC1005X55N]
C31  47pF  [CAPC1005X55N]
C32  47pF  [CAPC1005X55N]
C33  20pF  [CAPC1608X90N]
C34  20pF  [CAPC1608X90N]
C35  100nF  [CAPC1005X55N]
C36  100nF  [CAPC1005X55N]
C37  10uF  [CAPC1005X55N]
C38  100nF  [CAPC1005X55N]
C39  100nF  [CAPC1005X55N]
C40  10uF  [CAPC1005X55N]
C41  100nF  [CAPC1005X55N]
C42  100nF  [CAPC1005X55N]
D4  597-3301-507F  [LEDM3020X130N]
D5  597-3401-507F  [LEDM3020X130N]
D6  597-3301-507F  [LEDM3020X130N]
D7  597-3401-507F  [LEDM3020X130N]
J16  KMMX-ABSMT5SG-30TR  [KYCON_KMMX-ABSMT5]
J17  0022284060  [MOLEX_0022284060]
L2  220  [INDC2013X110N]
L3  744231121  [FIL_DLW21H]
L4  220  [INDC2013X110N]
R132  0  [RESC1609X55N]
R133  0  [RESC1609X55N]
R134  0  [RESC1609X55N]
R135  0  [RESC1609X55N]
R136  0  [RESC1609X55N]
R137  12K  [RESC1609X55N]
R138  22  [RESC1005X40N]
R139  22  [RESC1005X40N]
R140  20K  [RESC1609X55N]
R141  0  [RESC1609X55N]
R142  0  [RESC1609X55N]
R143  120  [RESC1005X40N]
R144  120  [RESC1005X40N]
R145  1.5K  [RESC1005X40N]
R146  0  [RESC1609X55N]
R147  0  [RESC1609X55N]
R148  120  [RESC1005X40N]
R149  470R 1%  [RESC0603X28N]
R150  120  [RESC1005X40N]
R151  0  [RESC1609X55N]
R152  0  [RESC1609X55N]
R153  0  [RESC1609X55N]
R154  0  [RESC1609X55N]
U8  AP2202  [SOT95P280X145-5N]
U9  FT2232D  [QFP50P900X900X160-48N]
X1  6MHz  [XTAL_ XT9M20HRR]

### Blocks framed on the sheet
Console  ports: C29-C42 D4-D7 J16 J17 L2-L4 R132-R154 U8 U9 X1

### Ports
CONSOLE_RX (bidir), CONSOLE_TX (bidir), UART4_RX (bidir), UART4_TX (bidir), XBEE2_UART_RX (bidir), XBEE2_UART_TX (bidir)

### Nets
3V3_DBG: C40.2 C41.2 C42.2 J17.1 R133.2 R134.2 R136.2 R143.1 R144.1 R148.1 R150.1 U9.10(SI/WUA) U9.14(VCCIOA) U9.26(SI/WUB) U9.31(VCCIOB)
3V3_SOM_EXT: R133.1
5V: R132.1
5V_DBG: C30.2 C37.2 C38.2 C39.2 R132.2 R135.2 R149.1 U8.1(VIN) U8.3(EN) U9.3(VCC) U9.4(RESET#) U9.42(VCC)
GND: C29.1 C30.1 C31.1 C32.1 C33.1 C34.1 C35.1 C36.2 C37.1 C38.1 C39.1 C40.1 C41.1 C42.1 J16.6(MNT1) J16.7(MNT2) J16.8(MNT3) J16.9(MNT4) J17.6 L4.2 R140.1 U8.2(GND) U9.9(GND) U9.18(GND) U9.25(GND) U9.34(GND) U9.45(AGND) U9.47(TEST)
CONSOLE_RX: J17.3 R141.2 ; port CONSOLE_RX
CONSOLE_TX: J17.2 R142.2 ; port CONSOLE_TX
FT230_USB_N: R138.2 U9.8(USBDM)
FT230_USB_P: R139.2 R145.1 U9.7(USBDP)
FTDI_3V3_OUT: C36.1 R134.1 U9.6(3V3OUT)
UART4_RX: R153.1 R154.1 ; port UART4_RX
UART4_TX: R151.1 R152.1 ; port UART4_TX
UART_M7_RX: J17.5 R146.2 R153.2
UART_M7_TX: J17.4 R147.2 R151.2
XBEE2_UART_RX: R154.2 ; port XBEE2_UART_RX
XBEE2_UART_TX: R152.2 ; port XBEE2_UART_TX
NetC29_2: C29.2 R136.1 R137.2 U8.5(VOUT)
NetC31_2: C31.2 L3.3 R138.1
NetC32_2: C32.2 L3.2 R139.1
NetC33_2: C33.2 U9.43(XTIN) X1.2
NetC34_2: C34.2 U9.44(XTOUT) X1.1
NetC35_2: C35.2 R149.2 U9.46(AVCC)
NetD4_A: D4.A R143.2
NetD4_K: D4.K U9.12(ACBUS2)
NetD5_A: D5.A R144.2
NetD5_K: D5.K U9.11(ACBUS3)
NetD6_A: D6.A R148.2
NetD6_K: D6.K U9.28(BCBUS2)
NetD7_A: D7.A R150.2
NetD7_K: D7.K U9.27(BCBUS3)
NetJ16_1: J16.1 L2.1
NetJ16_2: J16.2 L3.4
NetJ16_3: J16.3 L3.1
NetJ16_5: J16.5 L4.1
NetL2_2: L2.2 R135.1
NetR137_1: R137.1 R140.2 U8.4(ADJ)
NetR141_1: R141.1 U9.24(ADBUS0)
NetR142_1: R142.1 U9.23(ADBUS1)
NetR145_2: R145.2 U9.5(RSTOUT#)
NetR146_1: R146.1 U9.40(BDBUS0)
NetR147_1: R147.1 U9.39(BDBUS1)

Not connected (* = marked no-connect by the designer): J16 4*; U9 1(EESK)* 2(EEDATA)* 13(ACBUS1)* 15(ACBUS0)* 16(ADBUS7)* 17(ADBUS6)* 19(ADBUS5)* 20(ADBUS4)* 21(ADBUS3)* 22(ADBUS2)* 29(BCBUS1)* 30(BCBUS0)* 32(BDBUS7)* 33(BDBUS6)* 35(BDBUS5)* 36(BDBUS4)* 37(BDBUS3)* 38(BDBUS2)* 41(PWREN#)* 48(EECS)*

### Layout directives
differential pair; net class DIFF90: FT230_USB_N, FT230_USB_P

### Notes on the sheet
- VOUT = 1.25* (1+R140/R137)
  = 1.25* (1+20K/12K)
  = 3.3V

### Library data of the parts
C29 = 1001303: CAP CER 2.2UF 16V 10% X5R 0603; Part_Type: Capacitor; Manufacturer: TDK Corporation; Manufacturer_Part_Number: C1608X5R1C225K080AB; Digi_PN: 14050730; Component_Life_Cycle_State: Reviewed; Area: 2,27; Project: Pinnacle
C30 = 1001167: CAP CER 1UF 10V 10% X5R 0402; Part_Type: Capacitor; Manufacturer: Murata; Manufacturer_Part_Number: GRM155R61A105KE15D; Digi_PN: 14050399; Component_Life_Cycle_State: Reviewed; Area: 0,95
C31 C32 = 1000007: CAP 47pF 50V 5% NP0 0402; Part_Type: Capacitor; Manufacturer: Murata; Manufacturer_Part_Number: GRM1555C1H470JA01D; Manufacturer_Alt_1: AVX Corporation; Manufacturer_Alt_1_Part_Number: 04025A470JAT2A; Note: 14050747 is Digi No. for GE WDNU; Digi_PN: 14050309; Component_Life_Cycle_State: CAD Reviewed; Area: 0,95; Project: KITT; Temp_Coef: C0G, NP0
C33 C34 = 1002726: CAP CER 20PF 50V C0G/NP0 0603; Part_Type: Capacitor; Manufacturer: Murata; Manufacturer_Part_Number: GRM1885C1H200JA01D; Digi_PN: 14050657; Component_Life_Cycle_State: Reviewed; Area: 2,27; Tolerance: 5%; Temp_Coef: C0G, NP0; Project: DIGI CC8X SOM
C35 C36 C38 C39 C41 C42 = 1000006: CAP 100nF 16V 10% X7R 0402; Part_Type: Capacitor; Manufacturer: Murata; Manufacturer_Part_Number: GRM155R71C104KA88D; Digi_PN: 14050552; Component_Life_Cycle_State: CAD Reviewed; Area: 0,95; Project: KITT; Tolerance: 10
C37 C40 = 1001168: CAP CER 10UF 10V 20% X5R 0402; Part_Type: Capacitor; Manufacturer: Samsung; Manufacturer_Part_Number: CL05A106MP5NUNC; Digi_PN: 14050689; Component_Life_Cycle_State: Reviewed; Area: 0,95; Project: CCWMX6_SBC board
D4 D6 = 1001189: LED GREEN 573NM 1208 SMD; Manufacturer: Dialight; Note: 17050846 = Digi PN for GE WDNU II; Digi_PN: 17050183; Component_Life_Cycle_State: Reviewed; Area: 6
D5 D7 = 1001188: LED YELLOW 588NM 1208 SMD; Manufacturer: Dialight; Note: 17050842 = Digi No. for GE WDNU; Digi_PN: 17050387; Component_Life_Cycle_State: Reviewed; Area: 6
J16 = 1001117: CONN RECEPT MICRO-USB TYPE AB R/A; Part_Type: Connector; Manufacturer: KYCON; Digi_PN: 18000401; Component_Life_Cycle_State: Reviewed; Area: 40
J17 = 1002721: CONN HEADER VERT 6POS 2.54MM; Part_Type: Connector; Manufacturer: Molex; Digi_PN: 0790004; Component_Life_Cycle_State: Pending; Area: 42,49
L2 = 1001174: FERRITE BEAD 220 OHM 2.0A 0805; Manufacturer: Wurth Electronics Inc; Manufacturer_Part_Number: 742792022; Digi_PN: 21000146; Component_Life_Cycle_State: Reviewed; Area: 4.24; Project: CCWMX6_SBC board
L3 = 1001173: CHOKE COM MODE 120 OHM .37A; Part_Type: Inductor; Manufacturer: Wurth Electronics Inc; Digi_PN: 21000143; Component_Life_Cycle_State: Reviewed; Area: 2,4
L4 = 1001174: FERRITE BEAD 220 OHM 2.0A 0805; Manufacturer: Wurth Electronics Inc; Manufacturer_Part_Number: 742792022; Digi_PN: 21000146; Component_Life_Cycle_State: Reviewed; Area: 4,24
R132-R136 R141 R142 R146 R147 R151-R154 = 1000208: as R63-R68 on sheet 06 - CCIMX8M Nano RF, PCIe
R137 = 1001200: RES 12.0K OHM 1/10W 1% 0603 SMD; Part_Type: Resistor; Manufacturer: Yageo; Manufacturer_Part_Number: RC0603FR-0712KL; Digi_PN: 13050531; Component_Life_Cycle_State: Reviewed; Area: 2,5; Project: LuCoV2; Power_WV_SRF: 100; Tolerance: 1
R138 R139 = 1000601: RES 22.0 OHM 1/10W 1% 0402 SMD; Part_Type: Resistor; Manufacturer: Panasonic - ECG; Manufacturer_Part_Number: ERJ-2RKF22R0X; Digi_PN: 13051089; Component_Life_Cycle_State: CAD Reviewed; Area: 0,95; Project: KITT; Power_WV_SRF: 100
R140 = 1000142: RES 20K OHM 1/10W 5% 0603 SMD; Part_Type: Resistor; Manufacturer: Panasonic - ECG; Manufacturer_Part_Number: ERJ-3GEYJ203V; Digi_PN: 13050013; Component_Life_Cycle_State: Reviewed; Area: 2,5; Project: Adjustable Foundation; Power_WV_SRF: 100; Tolerance: 5
R143 R144 R148 R150 = 1001158: RES 120 OHM 1/16W 1% 0402 SMD; Part_Type: Resistor; Manufacturer: Yageo; Manufacturer_Part_Number: RC0402FR-07120RL; Digi_PN: 13050832; Component_Life_Cycle_State: Reviewed; Area: 0.95; Project: CCWMX6_SBC board; Note: 13051102 = Digi No. for GE WDNU
R145 = 1001772: SMRES, 1.5K OHM 0.063W 0402 1%; Part_Type: Resistor; Manufacturer: Vishay Dale; Manufacturer_Part_Number: CRCW04021K50FKED; Digi_PN: 13050862; Component_Life_Cycle_State: Reviewed; Area: 2,2; Power_WV_SRF: 63
R149 = 1001000: RES 470 OHM 1/20W 1% 0201 SMD; Part_Type: Resistor; Manufacturer: KOA; Manufacturer_Part_Number: RK73H1HTTC4700F; Manufacturer_Alt_1: Panasonic - ECG; Manufacturer_Alt_1_Part_Number: ERJ-1GNF4700C; Manufacturer_Alt_2_Part_Number: CRCW0201470RFKED; Digi_PN: 13050898; Component_Life_Cycle_State: Reviewed; Area: 0,18; Power_WV_SRF: 50; Tolerance: 1
U8 = 1001979: IC REG LDO ADJ 0.15A SOT25; Part_Type: Regulator; Manufacturer: Diodes, Inc.; Manufacturer_Part_Number: AP2202K-ADJTRG1; Digi_PN: 17050874; Component_Life_Cycle_State: Created; Area: 8,9; Project: iMX6UL+PMIC
U9 = 1002724: IC USB FS DUAL UART/FIFO 48-LQFP; Manufacturer: FTDI Chip; Digi_PN: 16000200; Component_Life_Cycle_State: Pending; Area: 98,01
X1 = 1002725: Crystals 6MHz lo-profile; Part_Type: Crystals-Oscillators; Manufacturer: Vishay Semiconductors; Manufacturer_Part_Number: XT9M20HRR6M; Digi_PN: 20000271; Component_Life_Cycle_State: Pending; Area: 89,92

## Sheet 09 - JTAG, SWD, uSD, Mini PCIe, uSIM.SchDoc: JTAG, SWD, uSD, Mini PCIe, uSIM
size A3; PageSetup: Record=PageOptions¦CenterHorizontal=True¦CenterVertical=True¦PrintScale=0.70¦XCorrection=1.00¦YCorrection=1.00¦PrintKind=0¦BorderSize=5000000¦LeftOffset=0¦BottomOffset=0¦Orientation=2¦PaperLength=4200¦PaperWidth=2970¦Scale=100¦PaperSource=7¦PrintQuality=600¦MediaType=1¦DitherType=10¦PaperKind=A4¦PrintScaleMode=1; Author: Juan Anzola; SheetNumber: 9; SheetTotal: 21

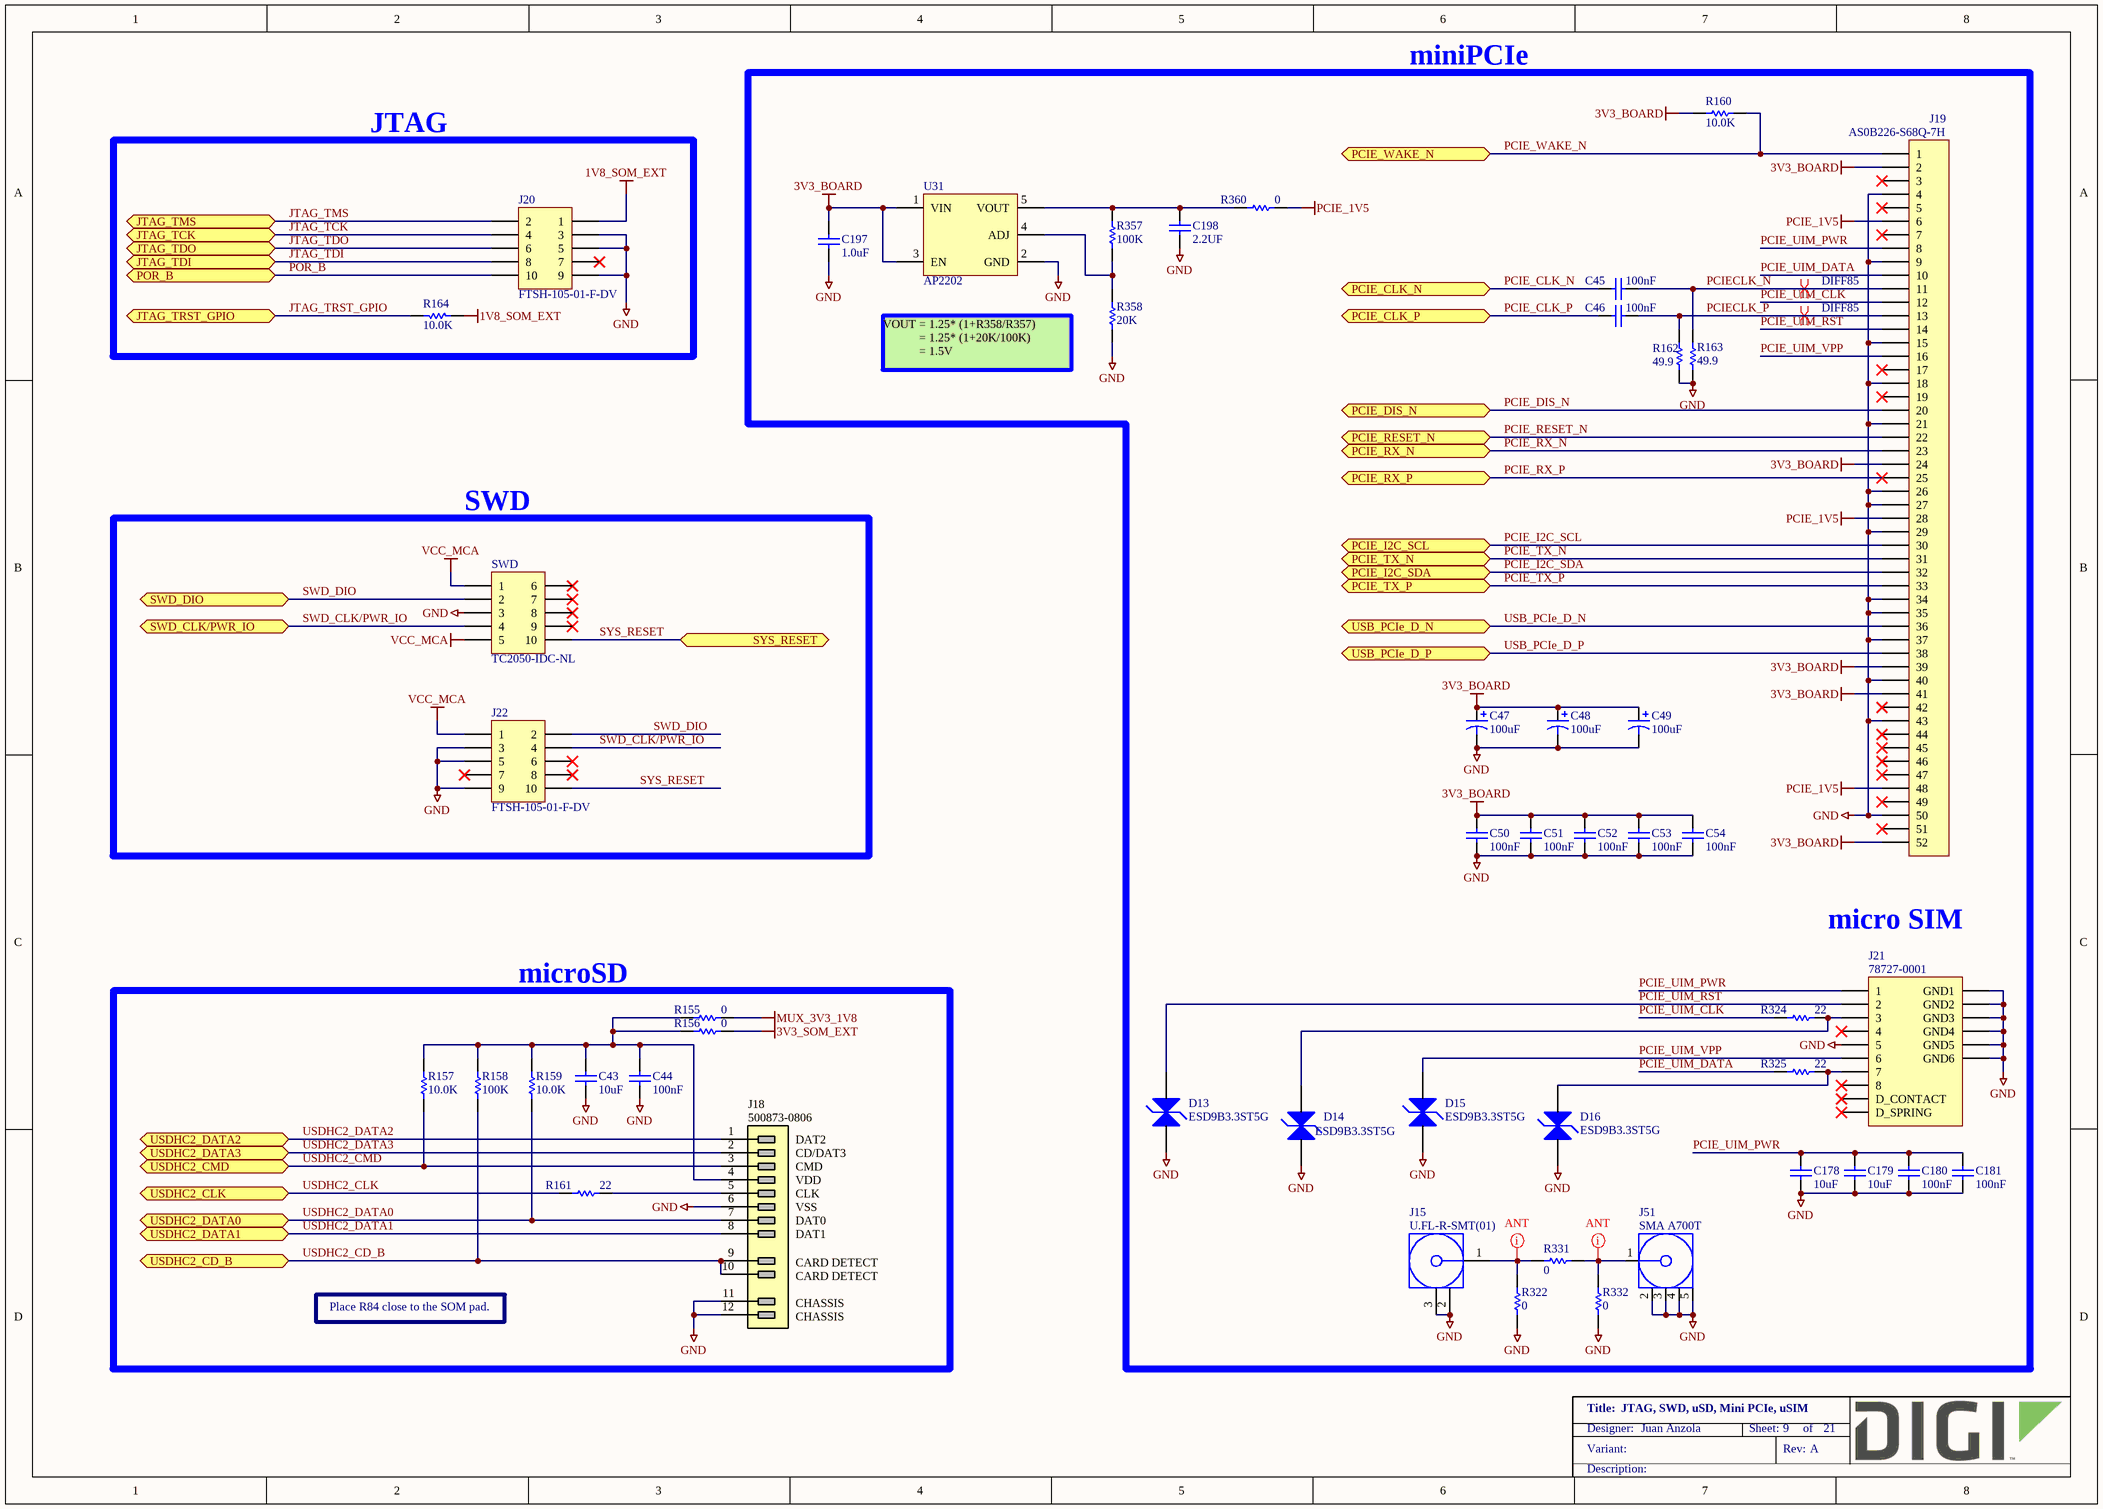
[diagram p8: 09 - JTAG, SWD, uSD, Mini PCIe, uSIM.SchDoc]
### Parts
C43  10uF  [CAPC1005X55N]
C44  100nF  [CAPC1005X55N]
C45  100nF  [CAPC1005X55N]
C46  100nF  [CAPC1005X55N]
C47  100uF  [CAPMP3216X120N]
C48  100uF  [CAPMP3216X120N]
C49  100uF  [CAPMP3216X120N]
C50  100nF  [CAPC1005X55N]
C51  100nF  [CAPC1005X55N]
C52  100nF  [CAPC1005X55N]
C53  100nF  [CAPC1005X55N]
C54  100nF  [CAPC1005X55N]
C178  10uF  [CAPC2013X135N]
C179  10uF  [CAPC2013X135N]
C180  100nF  [CAPC1005X55N]
C181  100nF  [CAPC1005X55N]
C197  1.0uF  [CAPC1005X55N]
C198  2.2UF  [CAPC1608X90N]
D13  ESD9B3.3ST5G  [SODFL1006X43AN12]
D14  ESD9B3.3ST5G  [SODFL1006X43AN12]
D15  ESD9B3.3ST5G  [SODFL1006X43AN12]
D16  ESD9B3.3ST5G  [SODFL1006X43AN12]
J15  U.FL-R-SMT(01)  [HIROSE_U.FL-R-SMT(01)]
J18  500873-0806  [MOLEX_500873-0806]
J19  Manufacturer_Part_Number: AS0B226-S68Q-7H  [FOXCONN_AS0B221-S68Q-7H]  (hidden comment: PCIe Minicard)
J20  FTSH-105-01-F-DV  [SAMTEC_FTSH-105-01-F-DV]
J21  78727-0001  [MOLEX_78727-0001]
J22  FTSH-105-01-F-DV  [SAMTEC_FTSH-105-01-F-DV]
J51  SMA A700T  [BOBBINTRON_SMA A700T]
R155  0  [RESC1005X40N]
R156  0  [RESC1005X40N]
R157  10.0K  [RESC1005X40N]
R158  100K  [RESC1005X40N]
R159  10.0K  [RESC1005X40N]
R160  10.0K  [RESC1005X40N]
R161  22  [RESC1005X40N]
R162  49.9  [RESC1005X40N]
R163  49.9  [RESC1005X40N]
R164  10.0K  [RESC1005X40N]
R322  0  [RESC1005X40N]
R324  22  [RESC1005X40N]
R325  22  [RESC1005X40N]
R331  0  [RESC1005X40N]
R332  0  [RESC1005X40N]
R357  100K  [RESC1005X40N]
R358  20K  [RESC1609X55N]
R360  0  [RESC1005X40N]
SWD  TC2050-IDC-NL  [TC_TC2050-IDC-NL]  (no BOM)
U31  AP2202  [SOT95P280X145-5N]

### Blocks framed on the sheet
JTAG: J20 R164
SWD: J22 SWD
microSD: C43 C44 J18 R155-R159 R161

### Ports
JTAG_TCK (bidir), JTAG_TDI (bidir), JTAG_TDO (bidir), JTAG_TMS (bidir), JTAG_TRST_GPIO (bidir), PCIE_CLK_N (bidir), PCIE_CLK_P (bidir), PCIE_DIS_N (bidir), PCIE_I2C_SCL (bidir), PCIE_I2C_SDA (bidir), PCIE_RESET_N (bidir), PCIE_RX_N (bidir), PCIE_RX_P (bidir), PCIE_TX_N (bidir), PCIE_TX_P (bidir), PCIE_WAKE_N (bidir), POR_B (bidir), SWD_CLK/PWR_IO (bidir), SWD_DIO (bidir), SYS_RESET (bidir), USB_PCIe_D_N (bidir), USB_PCIe_D_P (bidir), USDHC2_CD_B (bidir), USDHC2_CLK (bidir), USDHC2_CMD (bidir), USDHC2_DATA0 (bidir), USDHC2_DATA1 (bidir), USDHC2_DATA2 (bidir), USDHC2_DATA3 (bidir)

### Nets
1V8_SOM_EXT: J20.1 R164.1
3V3_BOARD: C47.1 C48.1 C49.1 C50.2 C51.2 C52.2 C53.2 C54.2 C197.1 J19.2 J19.24 J19.39 J19.41 J19.52 R160.2 U31.1(VIN) U31.3(EN)
3V3_SOM_EXT: R156.2
GND: C43.1 C44.1 C47.2 C48.2 C49.2 C50.1 C51.1 C52.1 C53.1 C54.1 C178.1 C179.1 C180.1 C181.1 C197.2 C198.1 D13.1 D14.1 D15.1 D16.1 J15.2(GND) J15.3(GND) J18.6 J18.11 J18.12 J19.4 J19.9 J19.15 J19.18 J19.21 J19.26 J19.27 J19.29 J19.34 J19.35 J19.37 J19.40 J19.43 J19.50 J20.3 J20.5 J20.9 J21.5 J21.11(GND1) J21.12(GND2) J21.13(GND3) J21.14(GND4) J21.15(GND5) J21.16(GND6) J22.3 J22.5 J22.9 J51.2(GND) J51.3(GND) J51.4(GND) J51.5(GND) R162.1 R163.1 R322.1 R332.1 R358.1 SWD.3 U31.2(GND)
MUX_3V3_1V8: R155.2
PCIE_1V5: J19.6 J19.28 J19.48 R360.2
VCC_MCA: J22.1 SWD.1 SWD.5
JTAG_TCK: J20.4 ; port JTAG_TCK
JTAG_TDI: J20.8 ; port JTAG_TDI
JTAG_TDO: J20.6 ; port JTAG_TDO
JTAG_TMS: J20.2 ; port JTAG_TMS
JTAG_TRST_GPIO: R164.2 ; port JTAG_TRST_GPIO
PCIE_CLK_N: C45.1 ; port PCIE_CLK_N
PCIE_CLK_P: C46.1 ; port PCIE_CLK_P
PCIE_DIS_N: J19.20 ; port PCIE_DIS_N
PCIE_I2C_SCL: J19.30 ; port PCIE_I2C_SCL
PCIE_I2C_SDA: J19.32 ; port PCIE_I2C_SDA
PCIE_RESET_N: J19.22 ; port PCIE_RESET_N
PCIE_RX_N: J19.23 ; port PCIE_RX_N
PCIE_RX_P: J19.25 ; port PCIE_RX_P
PCIE_TX_N: J19.31 ; port PCIE_TX_N
PCIE_TX_P: J19.33 ; port PCIE_TX_P
PCIE_UIM_CLK: J19.12 R324.1
PCIE_UIM_DATA: J19.10 R325.1
PCIE_UIM_PWR: C178.2 C179.2 C180.2 C181.2 J19.8 J21.1
PCIE_UIM_RST: D13.2 J19.14 J21.2
PCIE_UIM_VPP: D15.2 J19.16 J21.6
PCIE_WAKE_N: J19.1 R160.1 ; port PCIE_WAKE_N
PCIECLK_N: C45.2 J19.11 R163.2
PCIECLK_P: C46.2 J19.13 R162.2
POR_B: J20.10 ; port POR_B
SWD_CLK/PWR_IO: J22.4 SWD.4 ; port SWD_CLK/PWR_IO
SWD_DIO: J22.2 SWD.2 ; port SWD_DIO
SYS_RESET: J22.10 SWD.10 ; port SYS_RESET
USB_PCIe_D_N: J19.36 ; port USB_PCIe_D_N
USB_PCIe_D_P: J19.38 ; port USB_PCIe_D_P
USDHC2_CD_B: J18.9 J18.10 R158.2 ; port USDHC2_CD_B
USDHC2_CLK: R161.1 ; port USDHC2_CLK
USDHC2_CMD: J18.3 R157.1 ; port USDHC2_CMD
USDHC2_DATA0: J18.7 R159.1 ; port USDHC2_DATA0
USDHC2_DATA1: J18.8 ; port USDHC2_DATA1
USDHC2_DATA2: J18.1 ; port USDHC2_DATA2
USDHC2_DATA3: J18.2 ; port USDHC2_DATA3
NetC43_2: C43.2 C44.2 J18.4 R155.1 R156.1 R157.2 R158.1 R159.2
NetC198_2: C198.2 R357.2 R360.1 U31.5(VOUT)
NetD14_2: D14.2 J21.3 R324.2
NetD16_2: D16.2 J21.7 R325.2
NetJ15_1: J15.1(Signal) R322.2 R331.1
NetJ18_5: J18.5 R161.2
NetJ51_1: J51.1(Signal) R331.2 R332.2
NetR357_1: R357.1 R358.2 U31.4(ADJ)

Not connected (* = marked no-connect by the designer): J19 3* 5* 7* 17* 19* 42* 44* 45* 46* 47* 49* 51*; J20 7*; J21 4* 8* 9(D_CONTACT)* 10(D_SPRING)*; J22 6* 7* 8*; SWD 6* 7* 8* 9*

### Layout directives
differential pair; net class DIFF85: PCIECLK_N, PCIECLK_P
net class ANT: NetJ15_1, NetJ51_1

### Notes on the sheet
- miniPCIe
- VOUT = 1.25* (1+R358/R357)
  = 1.25* (1+20K/100K)
  = 1.5V
- micro SIM
- Place R84 close to the SOM pad.

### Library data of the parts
C43 = 1001168: CAP CER 10UF 10V 20% X5R 0402; Part_Type: Capacitor; Manufacturer: Samsung; Manufacturer_Part_Number: CL05A106MP5NUNC; Digi_PN: 14050689; Component_Life_Cycle_State: Reviewed; Area: 0.95; Project: CCWMX6_SBC board
C44 C50-C54 C180 C181 = 1000006: as C28 on sheet 07 - Bootstrap
C45 C46 = 1000006: as C35 on sheet 08 - Consoles
C47-C49 = 1001196: CAP TANT 100UF 6.3V 20% 1206; Part_Type: Capacitor; Manufacturer: Rohm; Manufacturer_Part_Number: TCTAL0J107M8R; Digi_PN: 14050490; Component_Life_Cycle_State: Reviewed; Area: 8.01; Project: CCWMX6_SBC board
C178 C179 = 1000111: CAP CER 10UF 16V 10% X5R 0805; Part_Type: Capacitor; Manufacturer: Murata; Manufacturer_Part_Number: GRM21BR61C106KE15L; Digi_PN: 14050701; Component_Life_Cycle_State: Proven; Area: 3.99; Project: Adjustable Foundation; Tolerance: 10
C197 = 1001167: as C30 on sheet 08 - Consoles
C198 = 1001303: CAP CER 2.2UF 16V 10% X5R 0603; Part_Type: Capacitor; Manufacturer: TDK Corporation; Manufacturer_Part_Number: C1608X5R1C225K080AB; Digi_PN: 14050730; Component_Life_Cycle_State: Reviewed; Area: 2,27
D13-D16 = 1001637: TVS DIODE 3.3VWM SOD923; Part_Type: Diodes; Manufacturer: On Semiconductor; Digi_PN: 17050883; Component_Life_Cycle_State: Reviewed; Area: 1,01
J15 = 1000027: as J10 on sheet 06 - CCIMX8M Nano RF, PCIe
J18 = 1001118: CONN TRANSFLSH R/A PUSH-PUSH SMD; Part_Type: Connector; Manufacturer: Molex; Digi_PN: MB03015; Component_Life_Cycle_State: Reviewed; Area: 213; Project: CCWMX6_SBC board
J19 = 1001130: SMCONN,MINI PCI EXP, 6.8MM HT; Part_Type: Connector; Manufacturer: Foxconn; Digi_PN: 18000349; Component_Life_Cycle_State: Reviewed; Area: 150; Project: CCWMX6_SBC board
J20 = 1000034: CONN HEADER 10POS DUAL .05" SMD; Part_Type: Connector; Manufacturer: Samtec; Note: 18000715 = Digi No. for GE WDNU; Digi_PN: 18000539; Component_Life_Cycle_State: Proven; Area: 43.55; Project: Adjustable Foundation
J21 = 1001120: MEMORY CARD 6POS PUSH/PULL SMD; Part_Type: Connector; Manufacturer: Molex; Digi_PN: 18000638; Component_Life_Cycle_State: Reviewed; Area: 217; Project: CCWMX6_SBC board
J22 = 1000034: CONN HEADER 10POS DUAL .05" SMD; Part_Type: Connector; Manufacturer: Samtec; Note: 18000715 = Digi No. for GE WDNU; Digi_PN: 18000539; Component_Life_Cycle_State: Proven; Area: 43,55; Project: Adjustable Foundation
J51 = 1002720: as J11 on sheet 06 - CCIMX8M Nano RF, PCIe
R155 R156 = 1000076: as R40 on sheet 06 - CCIMX8M Nano RF, PCIe
R157 R159 R160 R164 = 1000537: as R117 on sheet 07 - Bootstrap
R158 = 1000480: RES 100K OHM 1/10W 1% 0402 SMD; Part_Type: Resistor; Manufacturer: Panasonic - ECG; Manufacturer_Part_Number: ERJ-2RKF1003X; Digi_PN: 13051063; Component_Life_Cycle_State: CAD Reviewed; Area: 0.95; Project: KITT; Power_WV_SRF: 100
R161 R324 R325 = 1000601: RES 22.0 OHM 1/10W 1% 0402 SMD; Part_Type: Resistor; Manufacturer: Panasonic - ECG; Manufacturer_Part_Number: ERJ-2RKF22R0X; Digi_PN: 13051089; Component_Life_Cycle_State: CAD Reviewed; Area: 0,95; Power_WV_SRF: 100
R162 R163 = 1000466: RES 49.9 OHM 1/10W 1% 0402 SMD; Part_Type: Resistor; Manufacturer: Panasonic - ECG; Manufacturer_Part_Number: ERJ-2RKF49R9X; Digi_PN: 13051083; Component_Life_Cycle_State: CAD Reviewed; Area: 0,95; Project: KITT; Power_WV_SRF: 100
R322 R331 R332 R360 = 1000076: RES 0.0 OHM 1/10W 0402 SMD; Part_Type: Resistor; Manufacturer: Panasonic - ECG; Manufacturer_Part_Number: ERJ-2GE0R00X; Digi_PN: 13050387; Component_Life_Cycle_State: Proven; Area: 0,95; Power_WV_SRF: 10
R357 = 1000480: RES 100K OHM 1/10W 1% 0402 SMD; Part_Type: Resistor; Manufacturer: Panasonic - ECG; Manufacturer_Part_Number: ERJ-2RKF1003X; Digi_PN: 13051063; Component_Life_Cycle_State: CAD Reviewed; Area: 0,95; Power_WV_SRF: 100
R358 = 1000142: RES 20K OHM 1/10W 5% 0603 SMD; Part_Type: Resistor; Manufacturer: Panasonic - ECG; Manufacturer_Part_Number: ERJ-3GEYJ203V; Digi_PN: 13050013; Component_Life_Cycle_State: Reviewed; Area: 2,5; Power_WV_SRF: 100; Tolerance: 5
SWD = CAD0066: CBL PLUG-OF-NAILS 10-PIN; Part_Type: Test Point; Component_Life_Cycle_State: Created; Area: 8; Project: CCWMX6_SBC board
U31 = 1001979: IC REG LDO ADJ 0.15A SOT25; Part_Type: Regulator; Manufacturer: Diodes, Inc.; Manufacturer_Part_Number: AP2202K-ADJTRG1; Digi_PN: 17050874; Component_Life_Cycle_State: Reviewed; Area: 14,92

## Sheet 10 - RS485, CAN.SchDoc: RS485, CAN
size A3; PageSetup: Record=PageOptions¦CenterHorizontal=True¦CenterVertical=True¦PrintScale=0.70¦XCorrection=1.00¦YCorrection=1.00¦PrintKind=0¦BorderSize=5000000¦LeftOffset=0¦BottomOffset=0¦Orientation=2¦PaperLength=4200¦PaperWidth=2970¦Scale=100¦PaperSource=7¦PrintQuality=600¦MediaType=1¦DitherType=10¦PaperKind=A4¦PrintScaleMode=1; Author: Juan Anzola; SheetNumber: 10; SheetTotal: 21

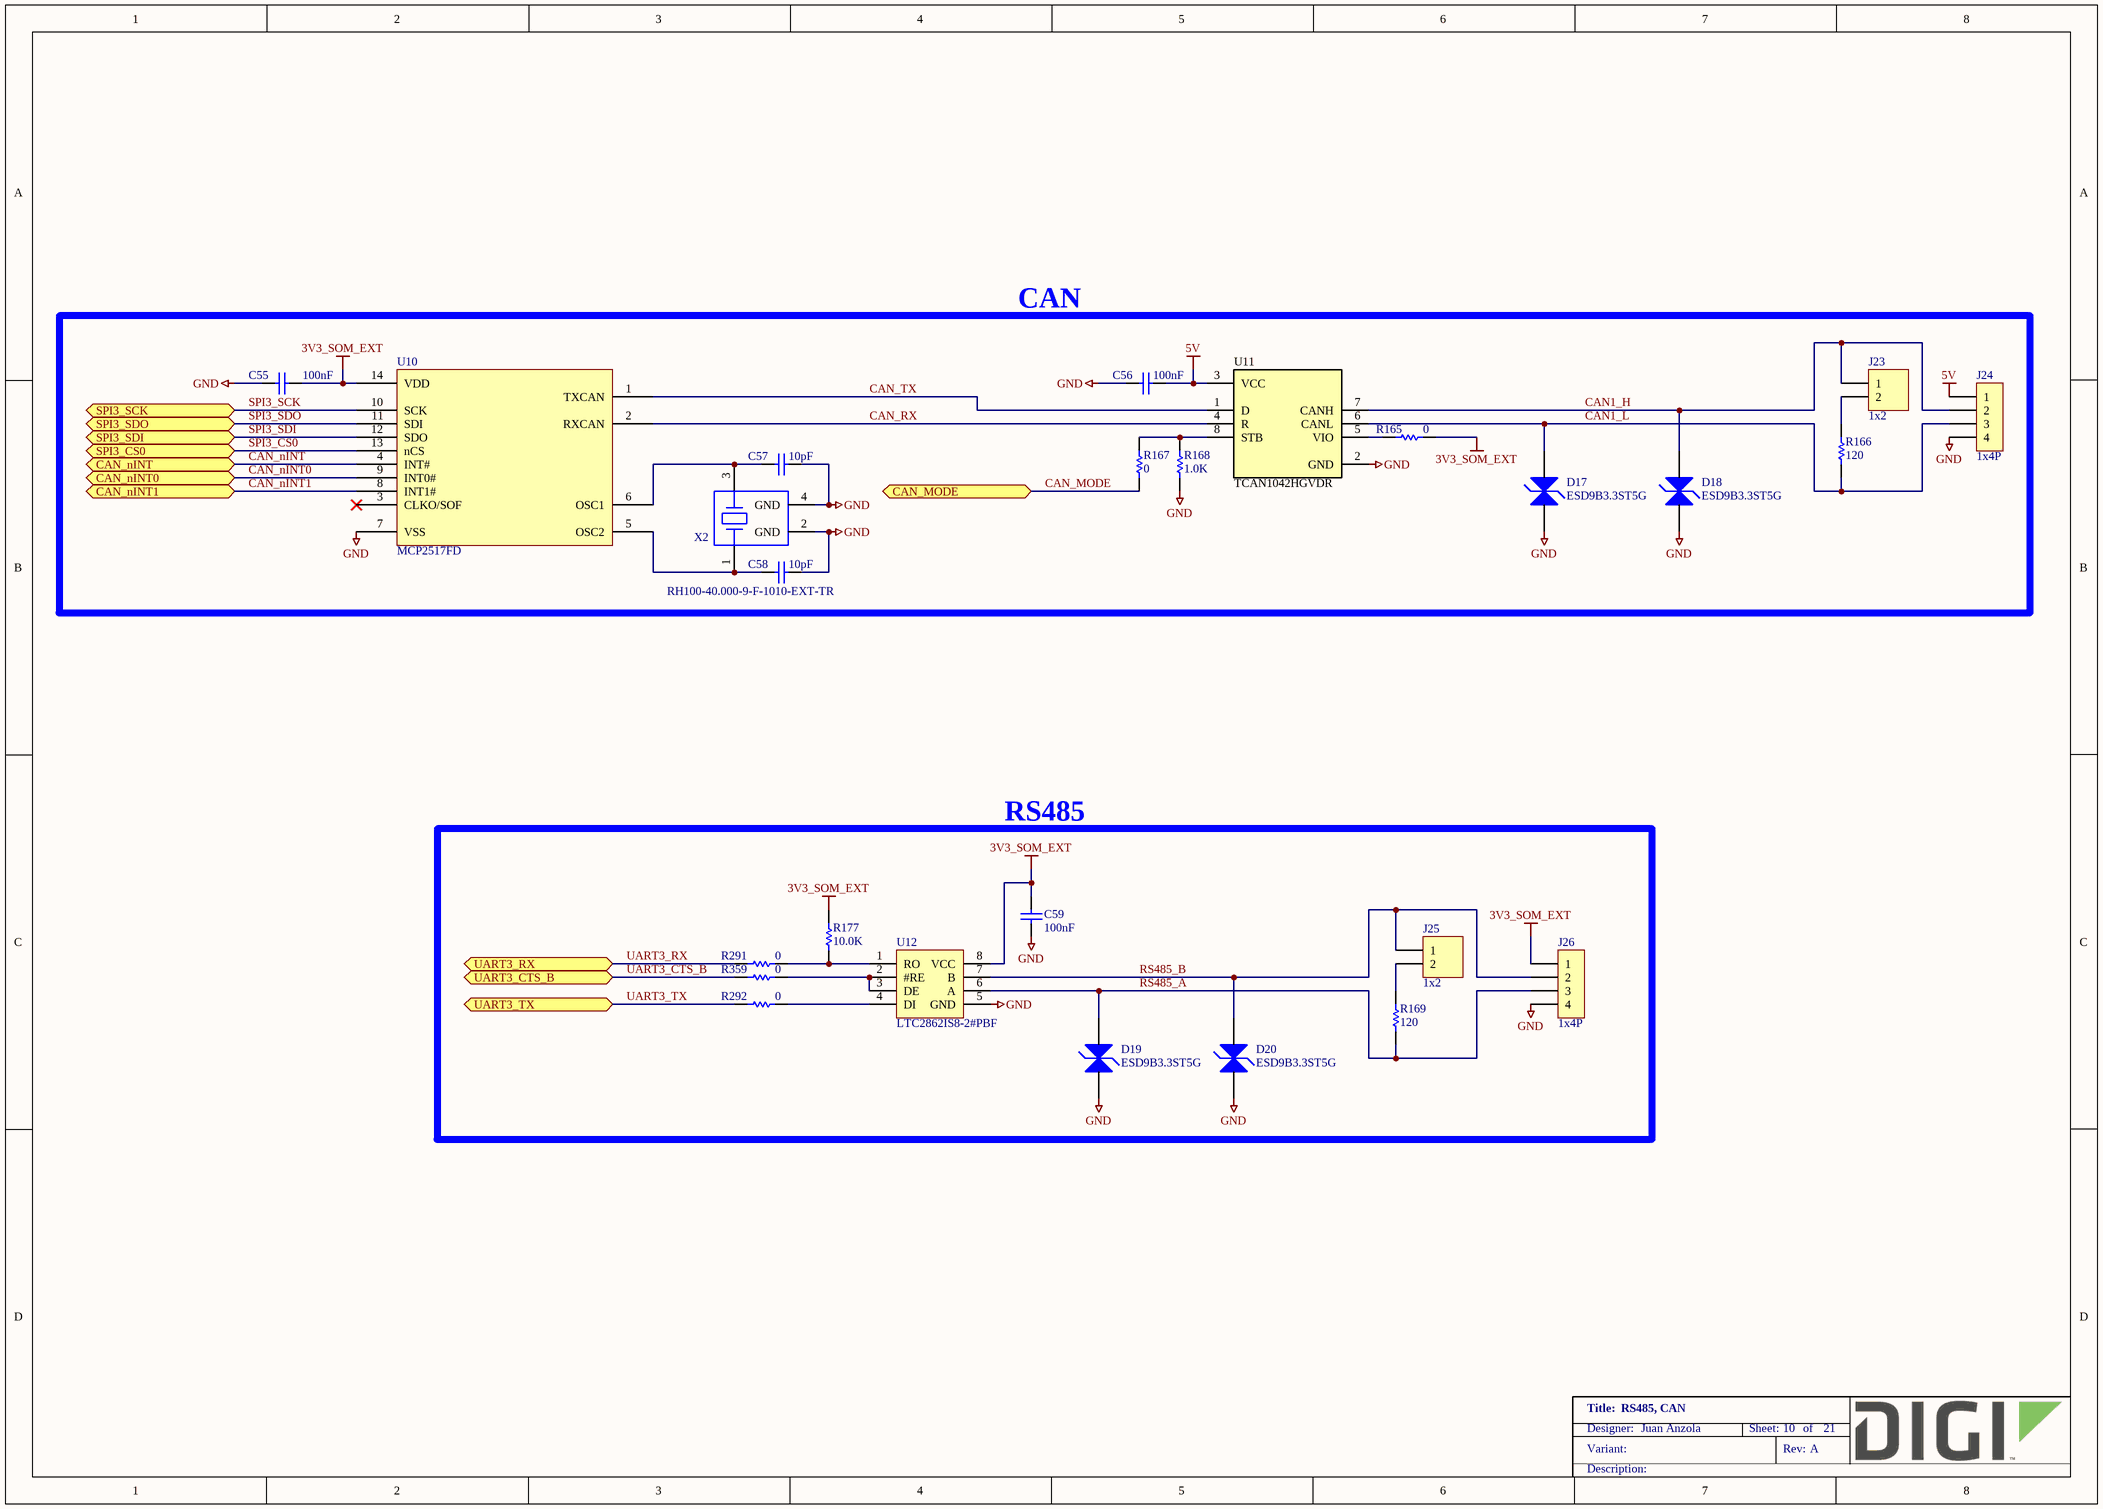
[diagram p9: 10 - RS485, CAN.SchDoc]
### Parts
C55  100nF  [CAPC1005X55N]
C56  100nF  [CAPC1005X55N]
C57  10pF  [CAPC1005X55N]
C58  10pF  [CAPC1005X55N]
C59  100nF  [CAPC1005X55N]
D17  ESD9B3.3ST5G  [SODFL1006X43AN12]
D18  ESD9B3.3ST5G  [SODFL1006X43AN12]
D19  ESD9B3.3ST5G  [SODFL1006X43AN12]
D20  ESD9B3.3ST5G  [SODFL1006X43AN12]
J23  1x2  [FCI_68002-102HLF]
J24  1x4P  [HDRV4W64P254_4X1_1016X248H1067]
J25  1x2  [FCI_68002-102HLF]
J26  1x4P  [HDRV4W64P254_4X1_1016X248H1067]
R165  0  [RESC1005X40N]
R166  120  [RESC1005X40N]
R167  0  [RESC1005X40N]
R168  1.0K  [RESC1005X40N]
R169  120  [RESC1005X40N]
R177  10.0K  [RESC1005X40N]
R291  0  [RESC1005X40N]
R292  0  [RESC1005X40N]
R359  0  [RESC1005X40N]
U10  MCP2517FD  [SOIC127P600X175-14N]
U11  TCAN1042HGVDR  [SOIC127P600X175-8N]
U12  LTC2862IS8-2#PBF  [SOIC127P600X175-8N]
X2  RH100-40.000-9-F-1010-EXT-TR  [OSCCC320X250X71N]

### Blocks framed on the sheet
RS485: C59 D19 D20 J25 J26 R169 R177 R291 R292 R359 U12

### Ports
CAN_MODE (bidir), CAN_nINT0 (bidir), CAN_nINT1 (bidir), CAN_nINT (bidir), SPI3_CS0 (bidir), SPI3_SCK (bidir), SPI3_SDI (bidir), SPI3_SDO (bidir), UART3_CTS_B (bidir), UART3_RX (bidir), UART3_TX (bidir)

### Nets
3V3_SOM_EXT: C55.1 C59.2 J26.1 R165.2 R177.2 U10.14(VDD) U12.8(VCC)
5V: C56.1 J24.1 U11.3(VCC)
GND: C55.2 C56.2 C57.1 C58.1 C59.1 D17.1 D18.1 D19.1 D20.1 J24.4 J26.4 R168.1 U10.7(VSS) U11.2(GND) U12.5(GND) X2.2(GND) X2.4(GND)
CAN1_H: D18.2 J23.1 J24.2 U11.7(CANH)
CAN1_L: D17.2 J24.3 R166.1 U11.6(CANL)
CAN_MODE: R167.1 ; port CAN_MODE
CAN_nINT: U10.4(INT#) ; port CAN_nINT
CAN_nINT0: U10.9(INT0#) ; port CAN_nINT0
CAN_nINT1: U10.8(INT1#) ; port CAN_nINT1
CAN_RX: U10.2(RXCAN) U11.4(R)
CAN_TX: U10.1(TXCAN) U11.1(D)
RS485_A: D19.2 J26.3 R169.1 U12.6(A)
RS485_B: D20.2 J25.1 J26.2 U12.7(B)
SPI3_CS0: U10.13(nCS) ; port SPI3_CS0
SPI3_SCK: U10.10(SCK) ; port SPI3_SCK
SPI3_SDI: U10.12(SDO) ; port SPI3_SDI
SPI3_SDO: U10.11(SDI) ; port SPI3_SDO
UART3_CTS_B: R359.1 ; port UART3_CTS_B
UART3_RX: R291.1 ; port UART3_RX
UART3_TX: R292.1 ; port UART3_TX
NetC57_2: C57.2 U10.6(OSC1) X2.3
NetC58_2: C58.2 U10.5(OSC2) X2.1
NetJ23_2: J23.2 R166.2
NetJ25_2: J25.2 R169.2
NetR165_1: R165.1 U11.5(VIO)
NetR167_2: R167.2 R168.2 U11.8(STB)
NetR177_1: R177.1 R291.2 U12.1(RO)
NetR292_2: R292.2 U12.4(DI)
NetR359_2: R359.2 U12.2(#RE) U12.3(DE)

Not connected (* = marked no-connect by the designer): U10 3(CLKO/SOF)*

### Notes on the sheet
- CAN
- (near U10) CAN

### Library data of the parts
C55 C56 C59 = 1000006: as C28 on sheet 07 - Bootstrap
C57 C58 = 1001541: CAP CER 10PF 50V 5% NP0 0402; Part_Type: Capacitor; Manufacturer: Murata; Manufacturer_Part_Number: GRM1555C1H100JA01D; Note: 14050750 = Digi No. for GE WDNU; Digi_PN: 14050362; Component_Life_Cycle_State: Reviewed; Area: 0,95; Project: KITT v0.4; Tolerance: 5; Temp_Coef: C0G, NP0
D17-D20 = 1001637: as D13 on sheet 09 - JTAG, SWD, uSD, Mini PCIe, uSIM
J23 J25 = 1001128: CONN HEADER 2POS .100" SGL GOLD; Part_Type: Connector; Manufacturer: Samtec; Manufacturer_Part_Number: TSW-102-07-G-S; Digi_PN: 00120002; Component_Life_Cycle_State: Reviewed; Area: 12,9032
J24 J26 = 1002743: CONN HEADER VERT 4POS 2.54MM; Part_Type: Connector; Manufacturer: Semtech; Manufacturer_Part_Number: TSW-104-14-G-S; Digi_PN: 18050278; Component_Life_Cycle_State: Reviewed; Area: 31,77
R165 = 1000076: as R40 on sheet 06 - CCIMX8M Nano RF, PCIe
R166 R169 = 1001158: as R143 on sheet 08 - Consoles
R167 = 1000076: as R51 on sheet 06 - CCIMX8M Nano RF, PCIe
R168 = 1000079: RES 1.00K OHM 1/10W 1% 0402 SMD; Part_Type: Resistor; Manufacturer: Panasonic - ECG; Manufacturer_Part_Number: ERJ-2RKF1001X; Digi_PN: 13051085; Component_Life_Cycle_State: Proven; Area: 0,95; Project: Adjustable Foundation; Power_WV_SRF: 10
R177 = 1000537: as R117 on sheet 07 - Bootstrap
R291 R292 R359 = 1000076: as R322 on sheet 09 - JTAG, SWD, uSD, Mini PCIe, uSIM
U10 = 1002729: IC CANBUS CONTROLLER SPI 14SOIC; Manufacturer: Microchip; Manufacturer_Part_Number: MCP2517FD-H/SL; Digi_PN: 16000201; Component_Life_Cycle_State: Reviewed; Area: 69,04
U11 = 1002681: IC CAN TRANSEIVER HS 8SOIC; Manufacturer: Texas Instruments; Digi_PN: 16000166; Component_Life_Cycle_State: Pending; Area: 20; Project: DIGI CC8X SOM
U12 = 1001420: IC TRANSCEIVER RS485 8-SOIC; Manufacturer: Linear Technology; Digi_PN: 16052092; Component_Life_Cycle_State: Reviewed; Area: 34.75; Project: E-Gear Gateway v0.1
X2 = 1002203: CRYSTAL 40.0000MHz 9pF -40°C - 85°C DFN LCC; Part_Type: Crystals-Oscillators; Manufacturer: Raltron; Digi_PN: 20000303; Component_Life_Cycle_State: Reviewed; Area: 14,92

## Sheet 11 - Ethernet.SchDoc: Ethernet
size A3; PageSetup: Record=PageOptions¦CenterHorizontal=True¦CenterVertical=True¦PrintScale=0.70¦XCorrection=1.00¦YCorrection=1.00¦PrintKind=0¦BorderSize=5000000¦LeftOffset=0¦BottomOffset=0¦Orientation=2¦PaperLength=4200¦PaperWidth=2970¦Scale=100¦PaperSource=7¦PrintQuality=600¦MediaType=1¦DitherType=10¦PaperKind=A4¦PrintScaleMode=1; Author: Juan Anzola; SheetNumber: 11; SheetTotal: 21

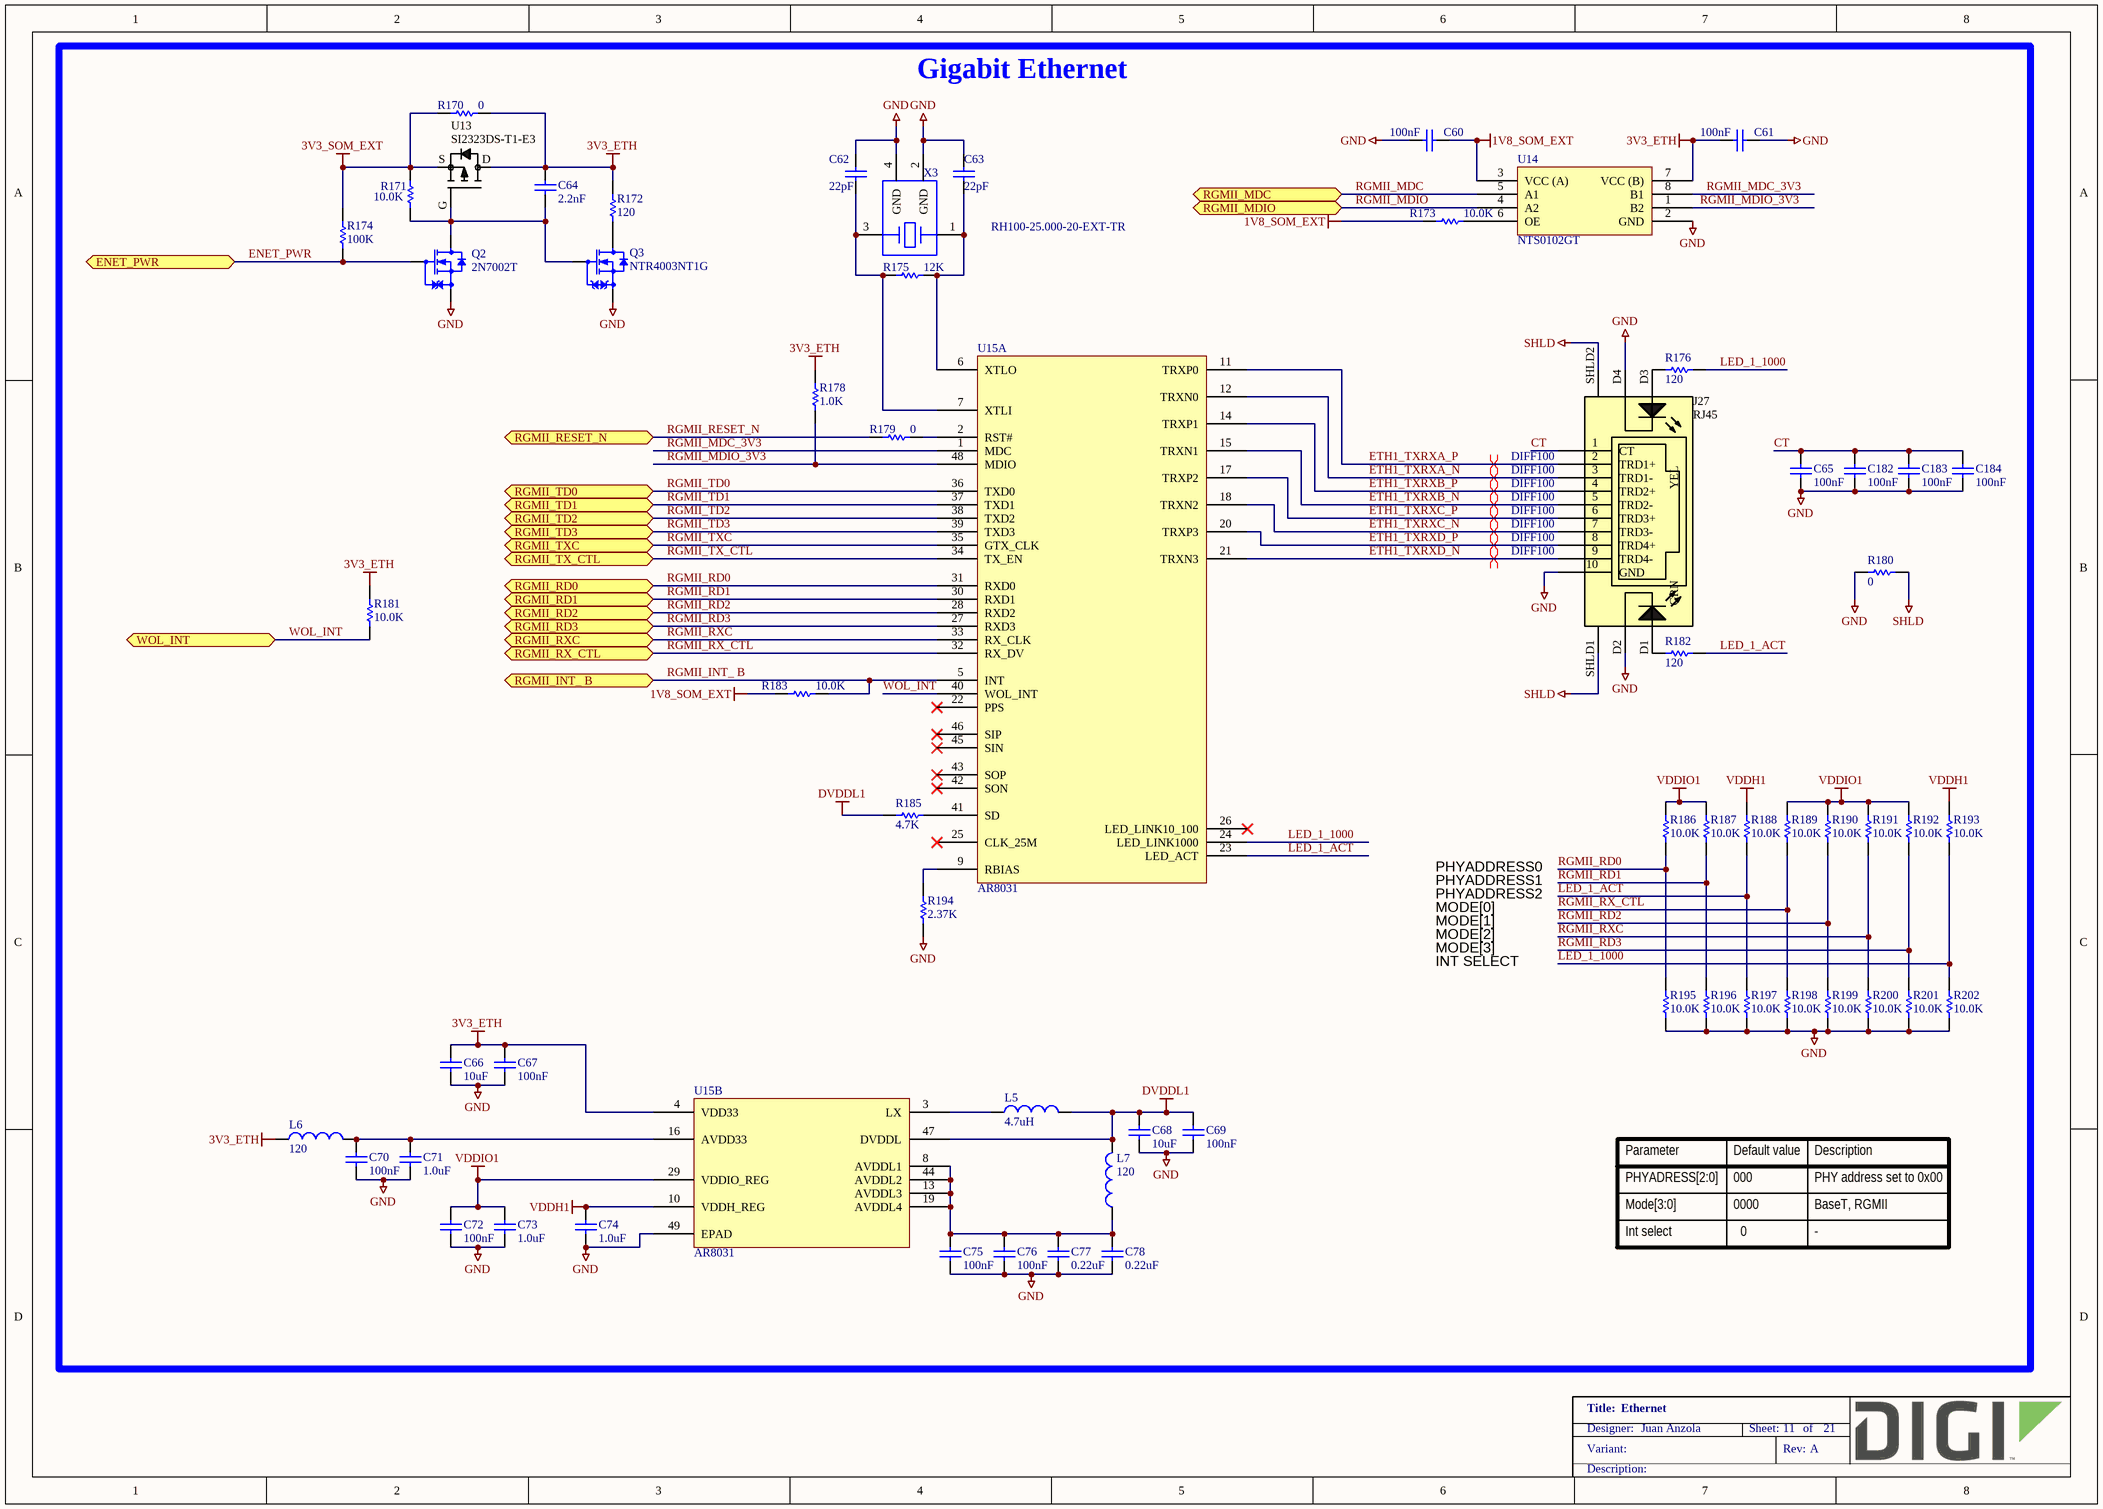
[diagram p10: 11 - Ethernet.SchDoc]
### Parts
C60  100nF  [CAPC1005X55N]
C61  100nF  [CAPC1005X55N]
C62  22pF  [CAPC1005X55N]
C63  22pF  [CAPC1005X55N]
C64  2.2nF  [CAPC1608X90N]
C65  100nF  [CAPC1005X55N]
C66  10uF  [CAPC1005X55N]
C67  100nF  [CAPC1005X55N]
C68  10uF  [CAPC1005X55N]
C69  100nF  [CAPC1005X55N]
C70  100nF  [CAPC1005X55N]
C71  1.0uF  [CAPC1005X55N]
C72  100nF  [CAPC1005X55N]
C73  1.0uF  [CAPC1005X55N]
C74  1.0uF  [CAPC1005X55N]
C75  100nF  [CAPC1005X55N]
C76  100nF  [CAPC1005X55N]
C77  0.22uF  [CAPC1005X55N]
C78  0.22uF  [CAPC1005X55N]
C182  100nF  [CAPC1005X55N]
C183  100nF  [CAPC1005X55N]
C184  100nF  [CAPC1005X55N]
J27  RJ45  [XMULTIPLE_XMG-J1B211]
L5  4.7uH  [INDC2520X100L60N]
L6  120  [INDC1005X60N]
L7  120  [INDC1005X60N]
Q2  2N7002T  [SOTFL50P160X80_GSD-3N]
Q3  NTR4003NT1G  [SOT95P240X110_GSD-3N]
R170  0  [RESC1609X55N]
R171  10.0K  [RESC1005X40N]
R172  120  [RESC1005X40N]
R173  10.0K  [RESC1005X40N]
R174  100K  [RESC1005X40N]
R175  12K  [RESC1609X55N]
R176  120  [RESC1005X40N]
R178  1.0K  [RESC1005X40N]
R179  0  [RESC1005X40N]
R180  0  [RESC3225X60N]
R181  10.0K  [RESC1005X40N]
R182  120  [RESC1005X40N]
R183  10.0K  [RESC1005X40N]
R185  4.7K  [RESC1005X40N]
R186  10.0K  [RESC1005X40N]
R187  10.0K  [RESC1005X40N]
R188  10.0K  [RESC1005X40N]
R189  10.0K  [RESC1005X40N]
R190  10.0K  [RESC1005X40N]
R191  10.0K  [RESC1005X40N]
R192  10.0K  [RESC1005X40N]
R193  10.0K  [RESC1005X40N]
R194  2.37K  [RESC1005X40N]
R195  10.0K  [RESC1005X40N]
R196  10.0K  [RESC1005X40N]
R197  10.0K  [RESC1005X40N]
R198  10.0K  [RESC1005X40N]
R199  10.0K  [RESC1005X40N]
R200  10.0K  [RESC1005X40N]
R201  10.0K  [RESC1005X40N]
R202  10.0K  [RESC1005X40N]
U13  SI2323DS-T1-E3  [SOT95P240X110_GSD-3N]
U14  NTS0102GT  [PSON50P195X100X50-8N]
U15  AR8031  [QFN40P600X600X80-49T380N]  (parts A,B of 2)
X3  RH100-25.000-20-EXT-TR  [OSC210P320X250X90-4N]

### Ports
ENET_PWR (bidir), RGMII_INT_ B (bidir), RGMII_MDC (bidir), RGMII_MDIO (bidir), RGMII_RD0 (bidir), RGMII_RD1 (bidir), RGMII_RD2 (bidir), RGMII_RD3 (bidir), RGMII_RESET_N (bidir), RGMII_RX_CTL (bidir), RGMII_RXC (bidir), RGMII_TD0 (bidir), RGMII_TD1 (bidir), RGMII_TD2 (bidir), RGMII_TD3 (bidir), RGMII_TX_CTL (bidir), RGMII_TXC (bidir), WOL_INT (bidir)

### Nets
1V8_SOM_EXT: C60.2 R173.1 R183.2 U14.3(VCC_(A))
3V3_ETH: C61.2 C64.2 C66.2 C67.2 L6.1 R170.2 R172.1 R178.2 R181.1 U13.D U14.7(VCC_(B)) U15.4(VDD33)
3V3_SOM_EXT: R170.1 R171.1 R174.1 U13.S
DVDDL1: C68.2 C69.2 L5.2 L7.2 R185.1 U15.47(DVDDL)
GND: C60.1 C61.1 C62.1 C63.1 C65.1 C66.1 C67.1 C68.1 C69.1 C70.1 C71.1 C72.1 C73.1 C74.1 C75.1 C76.1 C77.1 C78.1 C182.1 C183.1 C184.1 J27.10(GND) J27.D2 J27.D4 Q2.S Q3.S R180.1 R194.1 R195.1 R196.1 R197.1 R198.1 R199.1 R200.1 R201.1 R202.1 U14.2(GND) U15.49(EPAD) X3.2(GND) X3.4(GND)
SHLD: J27.SHLD1(SHLD) J27.SHLD2(SHLD) R180.2
VDDH1: C74.2 R188.2 R193.2 U15.10(VDDH_REG)
VDDIO1: C72.2 C73.2 R186.2 R187.2 R189.2 R190.2 R191.2 R192.2 U15.29(VDDIO_REG)
CT: C65.2 C182.2 C183.2 C184.2 J27.1(CT)
ENET_PWR: Q2.G R174.2 ; port ENET_PWR
ETH1_TXRXA_N: J27.3(TRD1-) U15.12(TRXN0)
ETH1_TXRXA_P: J27.2(TRD1+) U15.11(TRXP0)
ETH1_TXRXB_N: J27.5(TRD2-) U15.15(TRXN1)
ETH1_TXRXB_P: J27.4(TRD2+) U15.14(TRXP1)
ETH1_TXRXC_N: J27.7(TRD3-) U15.18(TRXN2)
ETH1_TXRXC_P: J27.6(TRD3+) U15.17(TRXP2)
ETH1_TXRXD_N: J27.9(TRD4-) U15.21(TRXN3)
ETH1_TXRXD_P: J27.8(TRD4+) U15.20(TRXP3)
LED_1_1000: R176.1 R193.1 R202.2 U15.24(LED_LINK1000)
LED_1_ACT: R182.1 R188.1 R197.2 U15.23(LED_ACT)
RGMII_INT_ B: R183.1 U15.5(INT) ; port RGMII_INT_ B
RGMII_MDC: U14.5(A1) ; port RGMII_MDC
RGMII_MDC_3V3: U14.8(B1) U15.1(MDC)
RGMII_MDIO: U14.4(A2) ; port RGMII_MDIO
RGMII_MDIO_3V3: R178.1 U14.1(B2) U15.48(MDIO)
RGMII_RD0: R186.1 R195.2 U15.31(RXD0) ; port RGMII_RD0
RGMII_RD1: R187.1 R196.2 U15.30(RXD1) ; port RGMII_RD1
RGMII_RD2: R190.1 R199.2 U15.28(RXD2) ; port RGMII_RD2
RGMII_RD3: R192.1 R201.2 U15.27(RXD3) ; port RGMII_RD3
RGMII_RESET_N: R179.1 ; port RGMII_RESET_N
RGMII_RX_CTL: R189.1 R198.2 U15.32(RX_DV) ; port RGMII_RX_CTL
RGMII_RXC: R191.1 R200.2 U15.33(RX_CLK) ; port RGMII_RXC
RGMII_TD0: U15.36(TXD0) ; port RGMII_TD0
RGMII_TD1: U15.37(TXD1) ; port RGMII_TD1
RGMII_TD2: U15.38(TXD2) ; port RGMII_TD2
RGMII_TD3: U15.39(TXD3) ; port RGMII_TD3
RGMII_TX_CTL: U15.34(TX_EN) ; port RGMII_TX_CTL
RGMII_TXC: U15.35(GTX_CLK) ; port RGMII_TXC
WOL_INT: R181.2 U15.40(WOL_INT) ; port WOL_INT
NetC62_2: C62.2 R175.1 U15.7(XTLI) X3.3
NetC63_2: C63.2 R175.2 U15.6(XTLO) X3.1
NetC64_1: C64.1 Q2.D Q3.G R171.2 U13.G
NetC70_2: C70.2 C71.2 L6.2 U15.16(AVDD33)
NetC75_2: C75.2 C76.2 C77.2 C78.2 L7.1 U15.8(AVDDL1) U15.13(AVDDL3) U15.19(AVDDL4) U15.44(AVDDL2)
NetJ27_D1: J27.D1 R182.2
NetJ27_D3: J27.D3 R176.2
NetL5_1: L5.1 U15.3(LX)
NetQ3_D: Q3.D R172.2
NetR173_2: R173.2 U14.6(OE)
NetR179_2: R179.2 U15.2(RST#)
NetR185_2: R185.2 U15.41(SD)
NetR194_2: R194.2 U15.9(RBIAS)

Not connected (* = marked no-connect by the designer): U15 22(PPS)* 25(CLK_25M)* 26(LED_LINK10_100)* 42(SON)* 43(SOP)* 45(SIN)* 46(SIP)*

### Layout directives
differential pair; net class DIFF100: ETH1_TXRXA_N, ETH1_TXRXA_P, ETH1_TXRXB_N, ETH1_TXRXB_P, ETH1_TXRXC_N, ETH1_TXRXC_P, ETH1_TXRXD_N, ETH1_TXRXD_P

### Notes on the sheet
- Gigabit Ethernet
- PHYADDRESS0
- PHYADDRESS1
- PHYADDRESS2
- MODE[0]
- MODE[1]
- MODE[2]
- MODE[3]
- INT SELECT
- Parameter
- PHYADRESS[2:0]
- Default value
- 000
- Description
- PHY address set to 0x00
- Mode[3:0]
- Int select
- 0000
- 0
- BaseT, RGMII
- -

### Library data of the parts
C60 C61 = 1000006: as C28 on sheet 07 - Bootstrap
C62 C63 = 1001166: CAP CER 22PF 50V 5% NP0 0402; Part_Type: Capacitor; Manufacturer: Murata; Manufacturer_Part_Number: GRM1555C1H220JA01D; Note: 14050749 = Digi No. for GE WDNU; Digi_PN: 14050367; Component_Life_Cycle_State: Reviewed; Area: 0,95; Project: CCWMX6_SBC board; Temp_Coef: C0G, NP0
C64 = 1002727: CAP CER 2200PF 50V X7R 5% 0603; Part_Type: Capacitor; Manufacturer: Kemet; Manufacturer_Part_Number: C0603C222J5RACTU; Digi_PN: 14050443; Component_Life_Cycle_State: Pending; Area: 2,27
C65 C67 C70 C72 C75 C76 C182-C184 = 1000006: as C35 on sheet 08 - Consoles
C66 C68 = 1001168: as C37 on sheet 08 - Consoles
C69 = 1000006: as C26 on sheet 06 - CCIMX8M Nano RF, PCIe
C71 C73 C74 = 1001167: CAP CER 1UF 10V 10% X5R 0402; Part_Type: Capacitor; Manufacturer: Murata; Manufacturer_Part_Number: GRM155R61A105KE15D; Digi_PN: 14050399; Component_Life_Cycle_State: Reviewed; Area: 0.95; Project: CCWMX6_SBC board
C77 C78 = 1001883: as C24 on sheet 06 - CCIMX8M Nano RF, PCIe
J27 = 1002612: CONN MAGJACK 1PORT 1000 BASE-T IND; Part_Type: Connector; Manufacturer: XMultiple; Manufacturer_Part_Number: XMG-J1B2211NPA-1-DIG; Digi_PN: 18000772; Component_Life_Cycle_State: Created; Area: 339.5; Project: DIGI CC8X SOM
L5 = 1002610: FIXED IND 4.7UH 1.1A 110 MOHM; Manufacturer: Samsung; Manufacturer_Part_Number: CIG22L4R7MNE; Digi_PN: 21000590; Component_Life_Cycle_State: Created; Area: 5; Project: DIGI CC8X SOM; Tolerance: 20%
L6 L7 = 1001175: FERRITE BEAD 120 OHM .35A 0402; Part_Type: Filter; Manufacturer: Wurth Electronics Inc; Manufacturer_Part_Number: 7427927112; Digi_PN: 21000128; Component_Life_Cycle_State: Reviewed; Area: 1,12; Project: CCWMX6_SBC board
Q2 = 1000715: MOSFET N-CH 60V 115MA SOT-523F; Part_Type: Transistor; Manufacturer: Fairchild Semiconductor; Digi_PN: 17050797; Component_Life_Cycle_State: CAD Reviewed; Area: 3.06; Project: SmartMeter2; Note: 17050841 = Digi No. for GE WDNU
Q3 = 1000306: MOSFET N-CH 30V 500MA SOT-23; Part_Type: Transistor; Manufacturer: On Semiconductor; Digi_PN: 17050809; Component_Life_Cycle_State: Proven; Area: 10,92; Project: Adjustable Foundation
R170 = 1000208: RES 0.0 OHM 1/10W 0603; Part_Type: Resistor; Manufacturer: Panasonic - ECG; Manufacturer_Part_Number: ERJ-3GEY0R00V; Note: 13051103 = Digi No. for GE WDNU; Digi_PN: 13050568; Component_Life_Cycle_State: Reviewed; Area: 2.5; Project: Adjustable Foundation; Voltage: 75V
R171 R173 = 1000537: as R117 on sheet 07 - Bootstrap
R172 R176 R182 = 1001158: as R143 on sheet 08 - Consoles
R174 = 1000480: as R158 on sheet 09 - JTAG, SWD, uSD, Mini PCIe, uSIM
R175 = 1001200: as R137 on sheet 08 - Consoles
R178 = 1000079: as R168 on sheet 10 - RS485, CAN
R179 = 1000076: as R40 on sheet 06 - CCIMX8M Nano RF, PCIe
R180 = 1000229: RES 0.0 OHM 1/2W 1210 SMD; Part_Type: Resistor; Manufacturer: Vishay Dale; Manufacturer_Part_Number: CRCW12100000Z0EA; Digi_PN: 13050962; Component_Life_Cycle_State: Proven; Area: 11,07; Project: Adjustable Foundation
R181 R183 R186-R193 R195-R202 = 1000537: RES 10.0K OHM 1/10W 1% 0402 SMD; Part_Type: Resistor; Manufacturer: Panasonic - ECG; Manufacturer_Part_Number: ERJ-2RKF1002X; Digi_PN: 13051084; Component_Life_Cycle_State: CAD Reviewed; Area: 0,95; Project: KITT; Power_WV_SRF: 100
R185 = 1000038: as R77 on sheet 07 - Bootstrap
R194 = 1000469: RES 2.37K OHM 1/10W 1% 0402 SMD; Part_Type: Resistor; Manufacturer: Panasonic - ECG; Manufacturer_Part_Number: ERJ-2RKF2371X; Component_Life_Cycle_State: Reviewed; Area: 0.95; Project: SDR Prototype RF Board; Power_WV_SRF: 100; Digi_PN: 13000089
U13 = 1001163: MOSFET P-CH 20V 3.7A SOT23-3; Part_Type: IC; Manufacturer: Vishay Siliconix; Digi_PN: 17050358; Component_Life_Cycle_State: Reviewed; Area: 10.92; Project: CCWMX6_SBC board
U14 = 1002597: IC TRANSLATING TXRX 8XSON; Manufacturer: NXP Semiconductors; Manufacturer_Part_Number: NTS0102GT,115; Digi_PN: 16000138; Component_Life_Cycle_State: Created; Area: 3,9; Project: DIGI CC8X SOM
U15 = 1002583: IC TRANSCEIVER ETHERNET 48-QFN; Manufacturer: Qualcomm Atheros, Inc.; Digi_PN: 16000123; Component_Life_Cycle_State: Reviewed; Area: 52.56; Project: DIGI CC8X SOM
X3 = 1001497: SMCRY,25MHZ 50PPM 20PF RH100 EXT; Part_Type: Crystals-Oscillators; Manufacturer: Raltron; Digi_PN: 20000285; Component_Life_Cycle_State: Reviewed; Area: 3,2; Project: CCWMX6_SBC board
